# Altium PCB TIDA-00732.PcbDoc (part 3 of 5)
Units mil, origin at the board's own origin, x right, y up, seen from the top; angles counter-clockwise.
Board outline 8994.78 x 4186 mil, 6 copper layers (Top Layer, GND1, PWR1, PWR2, GND2, Bottom Layer), stack 97.668 mil thick; 693 components, 463 nets, 2087 pads, 616 vias.

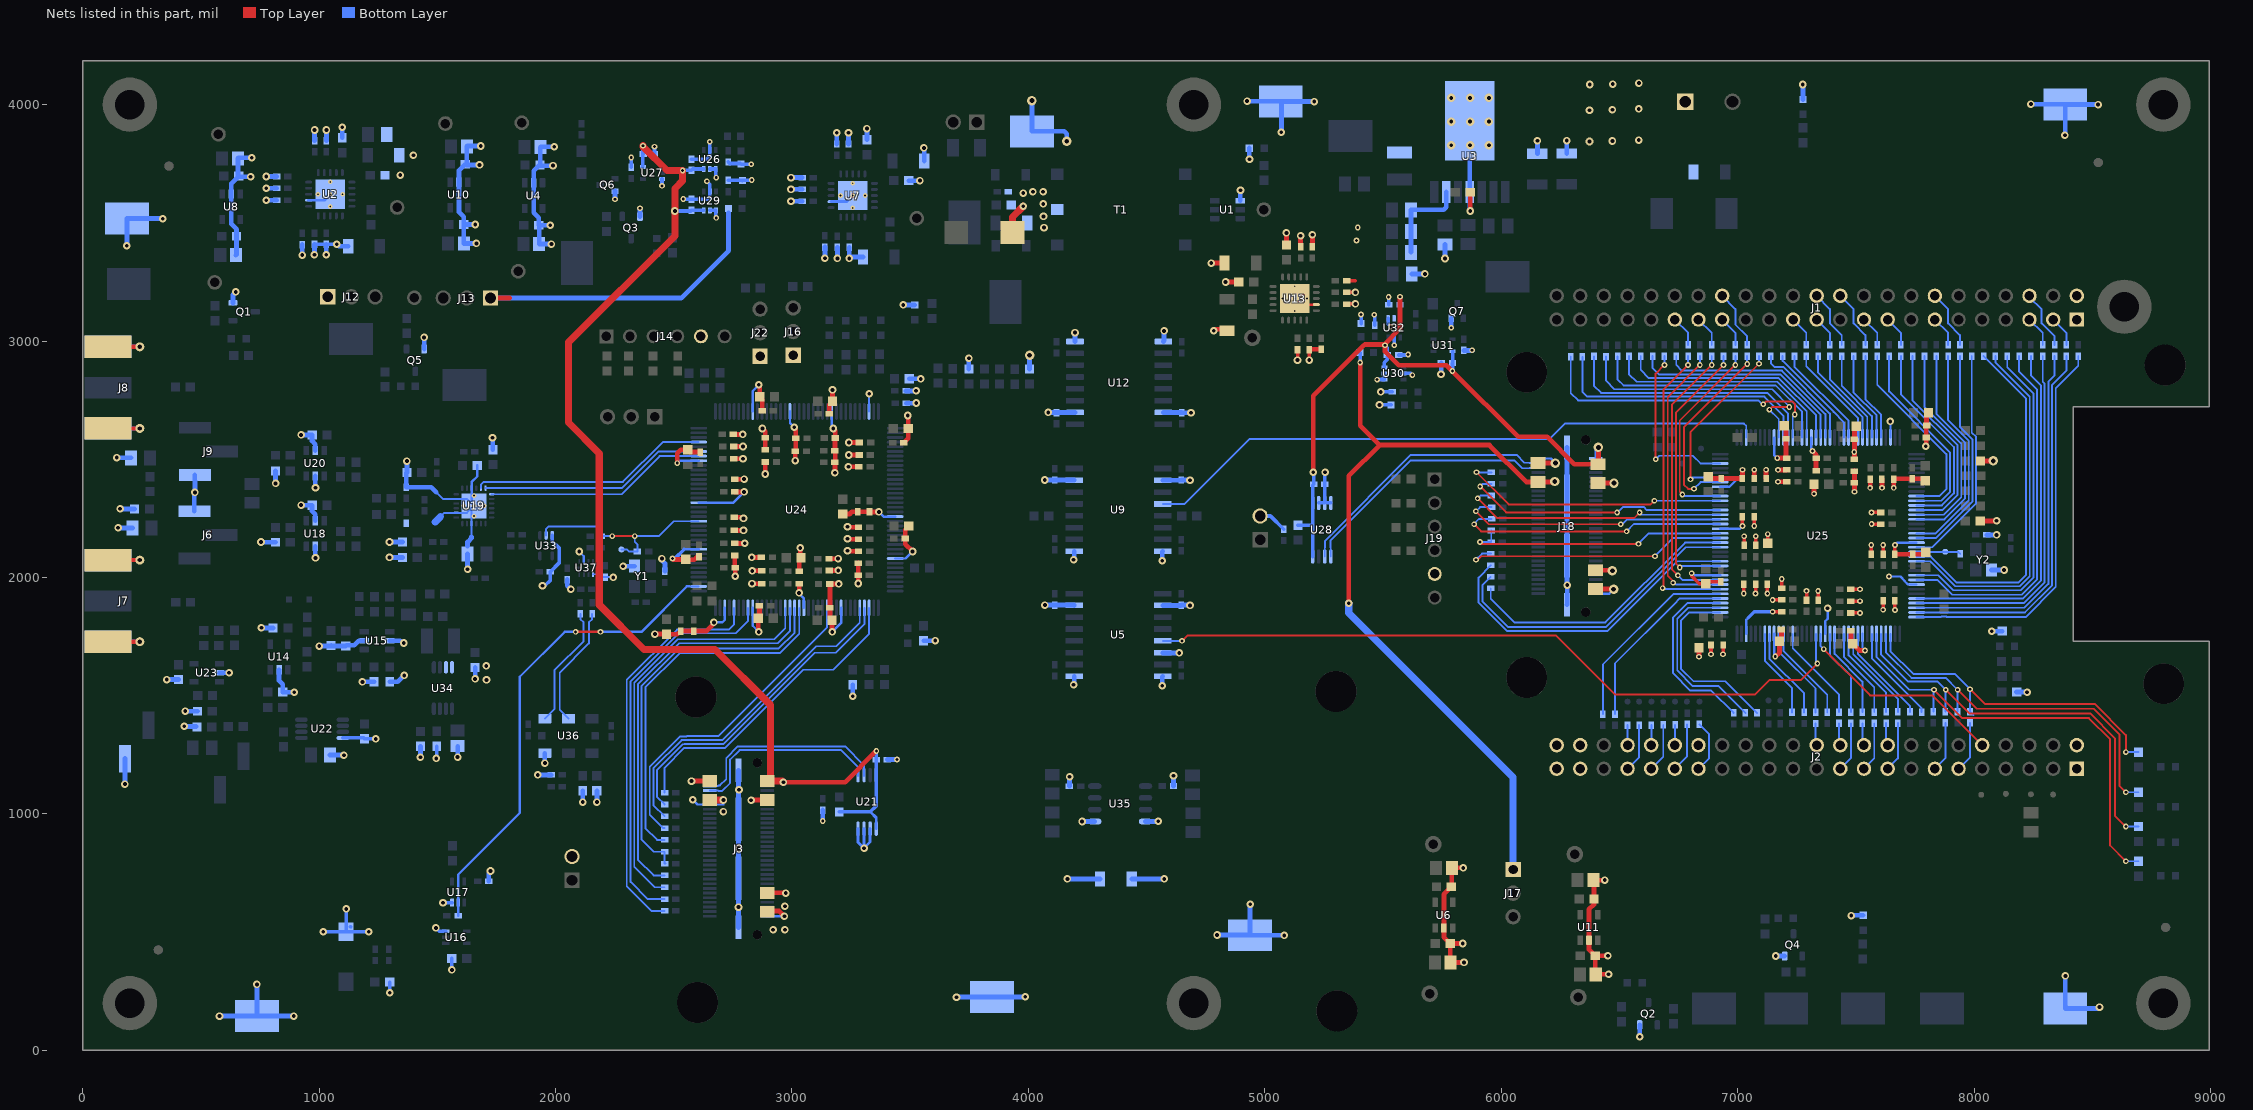
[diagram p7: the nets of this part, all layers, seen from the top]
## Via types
v1: diameter 32, hole 16, Top Layer to Bottom Layer, tented both sides, 393 vias
v2: diameter 24, hole 12, Top Layer to Bottom Layer, tented both sides, 174 vias
v3: diameter 19.68, hole 7.87, Top Layer to Bottom Layer, tented both sides, 20 vias
v4: diameter 40, hole 20, Top Layer to Bottom Layer, tented both sides, 19 vias
v5: diameter 36, hole 16, Top Layer to Bottom Layer, tented both sides, 9 vias
v6: diameter 24, hole 12, Top Layer to Bottom Layer, 1 vias

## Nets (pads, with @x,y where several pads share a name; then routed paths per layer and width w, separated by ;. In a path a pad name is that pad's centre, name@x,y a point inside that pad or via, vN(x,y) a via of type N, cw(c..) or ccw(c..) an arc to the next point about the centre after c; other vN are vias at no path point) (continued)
ADC_SDO1: U19.19 U24.138 | length 942.6
  Bottom Layer w8: U19.19@1729.8,2352.21 2279.21,2352.21 2440.38,2513.38 U24.138@2605.65,2513.38
ADC_SDO2: U19.18 U24.139 | length 965.7
  Bottom Layer w8: U19.18@1704.21,2377.8 2281.01,2377.8 2436.27,2533.06 U24.139@2605.65,2533.06
ADC_SDO3: U19.17 U24.141 | length 1010.6
  Bottom Layer w8: U19.17@1684.53,2377.8 1684.53,2393 1695.52,2404 2285,2404 2453.43,2572.43 U24.141@2605.65,2572.43
ADC_SRESETN: R93.1 U17.2 U24.110 | length 2034.4
  Top Layer w10: v2(2085,1770) v2(2190,1770)
  Bottom Layer w8: 2566.73,1962.2 U24.110@2605.65,1962.2
  Bottom Layer w10: R93.1@1587.75,568.73 1588.13,569.11 U17.2@1588.13,624.94 1588.13,743.1 1849,1003.97 1849,1580 2039,1770 v2(2085,1770) ; v2(2190,1770) 2363,1770 2555.2,1962.2 2566.73,1962.2
AGND_ISO: C2.2 C3.1 C4.2 C5.2 C6.2 C7.2 C9.2 C10.1 C12.2 C17.2 C18.2 C19.2 C20.2 C21.2 C22.2 C23.2 C24.1 C26.2 C31.2 C32.2 C33.2 C34.2 C35.2 C36.2 C37.2 C38.2 C44.1 C49.1 C50.1 C51.1 C53.2 C54.2 C55.1 C56.2 C57.2 C58.2 C59.2 C62.2 C63.1 C64.2 C65.2 C66.2 C69.2 C70.2 C71.2 C72.2 C75.1 C76.2 C77.1 C78.1 C79.2 C80.2 C81.2 C82.2 C83.2 C84.2 C85.2 C88.1 C92.2 C93.2 C94.2 C95.2 C96.2 C97.2 C98.2 C99.2 C100.2 C101.2 C102.2 C103.2 C104.2 C105.2 C106.2 C107.2 C108.2 C109.2 C110.2 C111.2 C112.2 C113.2 C114.2 C115.2 C116.2 C117.2 C118.2 C119.2 C120.2 C121.2 C122.2 C123.2 C124.2 C125.2 C126.2 C127.2 C128.1 C129.2 C130.2 C131.2 C132.2 C133.1 C134.2 C135.2 C136.2 C137.2 C138.2 C139.2 C140.2 C141.2 C142.2 C143.2 C144.2 C145.2 C146.2 C147.2 C148.2 C149.2 C150.2 C151.2 C152.2 C153.2 C154.2 C155.1 C192.1 C197.2 C219.1 C221.2 C228.1 C230.2 C231.2 C232.2 C233.2 C236.1 C237.2 D13.1 J3.60 J3.MP1 J3.MP2 J3.MP3 J3.MP4 J4.2 J6.1 J7.2 J7.3 J7.4 J7.5 J8.2 J8.3 J8.4 J8.5 J9.3 J11.2 J14.5 J16.1 J22.1 Q1.2 Q3.2 Q5.2 Q6.2 R46.2 R47.1 R53.1 R54.1 R55.1 R56.1 R57.1 R58.1 R59.1 R60.1 R64.1 R65.1 R66.1 R67.1 R68.1 R69.1 R70.1 R71.1 R88.1 R91.1 R96.1 R114.1 R158.1 R165.1 R168.1 R177.2 R249.1 R250.1 R253.1 R267.1 S1.1 T1.5 TP36.1 TP37.1 TP38.1 TP39.1 U2.7 U2.21 U4.2 U5.9 U5.15 U7.7 U7.21 U8.2 U9.9 U9.15 U10.2 U12.2 U12.8 U14.2 U15.2 U15.5 U16.3 U17.3 U18.2 U18.5 U19.4 U19.8 U19.11 U19.15 U19.25 U20.2 U20.5 U21.2 U21.3 U21.4 U22.4 U23.2 U24.9 U24.17 U24.26 U24.34 U24.56 U24.65 U24.81 U24.89 U24.100 U24.106 U24.118 U24.128 U24.137 U26.2 U27.3 U29.2 U33.3 U34.7 U34.8 U35.5 U36.3@1955,1257.17 U37.1 U37.7 Y1.2 | length 16929.3
  Top Layer w10: v1@2095,2110 v1(2100,2110)
  Top Layer w15: v2(2418.62,3822.38) v2@2420,3821 ; v2@2650,3841 v2(2652,3843)
  Top Layer w20: v1@1398.92,3785.92 v1(1399,3786) ; v1(2420.57,1760.57) C97.2@2469.36,1760.57 2470.42,1759.51 2515.43,1759.51 C101.2@2529.36,1773.44 C95.2@2584.36,1773.44 2638.44,1773.44 2670,1805 v1(2670,1810) ; v2(2495,2080) 2498.5,2076.5 C121.2@2551,2076.5 2552.5,2075 2586.5,2075 2599.88,2088.38 C114.2@2607,2088.38 ; v2(2515,2483.69) 2515,2525.5 2530,2540.5 C120.2@2559,2540.5 2568.87,2530.62 C113.2@2613,2530.62 ; v1(2575,1139) 2575.06,1138.94 C83.2@2652.5,1138.94 ; C115.2@2752.62,2605 v1(2792,2605) ; C127.2@2753.62,2502 v1(2793,2502) ; C126.2@2753.62,2554 v1(2793,2554) ; C109.2@2755.62,2199 v1(2795,2199) ; C103.2@2755.62,2255 2790,2255 v1(2795,2250) ; C100.2@2758.24,2362 v1(2797.62,2362) ; C94.2@2758.24,2416 v1(2797.62,2416) ; C124.2@2758.62,2093 2758.62,2043 C125.2@2759.62,2042 2759.62,2005.38 v1(2760,2005) ; C112.2@2758.62,2144 2799,2144 v1(2800,2145) ; v1(2827,1058) 2827.94,1058.94 C84.2@2895.5,1058.94 ; v1(2830,2085) C149.2@2870.38,2085 ; v1(2831,1974) C135.2@2871.38,1974 ; v1(2832,2028) C148.2@2872.38,2028 ; v1(2860,1770) 2857.57,1772.43 C142.2@2857.57,1827.36 2862.44,1832.24 C134.2@2862.44,1880.36 ; v1(2860,2815) 2863.5,2811.5 C145.2@2863.5,2765 2874.38,2754.13 C138.2@2874.38,2704.5 ; v1(2875,2630) 2887.38,2617.62 C141.2@2887.38,2591.5 2887.38,2541.5 C151.2@2886.38,2540.5 ; v1(2887.38,2437.62) C152.2@2887.38,2488.5 ; C82.2@2895.5,666.14 2972.86,666.14 v1(2974,665) ; v1(3010,2635) 3016.38,2628.62 C110.2@3016.38,2589.5 3016.38,2536.5 C104.2@3014.38,2534.5 v1(3014.38,2494.38) ; v1(3030,1935) 3030.62,1935.62 C108.2@3030.62,1974 ; C102.2@3030.62,2027 3030.62,2075.13 C106.2@3038.5,2083 3035,2086.5 v1(3035,2125) ; C147.2@3156.62,2079.5 3194.5,2079.5 v1(3195,2080) ; C146.2@3157.62,2029.5 3195.5,2029.5 v1(3196,2030) ; C140.2@3157.62,2692 3157.62,2731.13 C144.2@3171.5,2745 v1(3171.5,2793.5) ; v1(3170,1770) 3169.5,1770.5 C143.2@3169.5,1819 3160.62,1827.87 C136.2@3160.62,1872 3160.62,1971.5 C137.2@3159.62,1972.5 3197.5,1972.5 v1(3198,1973) ; v1(3175,2630) 3183.62,2621.38 C139.2@3183.62,2590 ; v1(3181.62,2442.62) C153.2@3181.62,2487 3183.62,2489 C139.2@3183.62,2590 ; C154.2@3181.62,2536 3181.62,2588 C139.2@3183.62,2590 ; C107.2@3215,2268.5 3243.5,2268.5 3253.38,2278.38 C111.2@3278,2278.38 3327,2278.38 C105.2@3328,2277.38 v1(3367.62,2277.38) ; v1(3235,2113) 3237,2111 C132.2@3281.38,2111 ; v1(3235,2164) 3237,2162 C131.2@3281.38,2162 ; v1(3235,2215) 3237,2213 C117.2@3281.38,2213 ; v1(3239,2468) C130.2@3283.38,2468 ; v1(3240,2518) C129.2@3284.38,2518 ; v1(3241,2571) C119.2@3285.38,2571 ; v1(3280.38,1974.62) C99.2@3280.38,2010 C93.2@3280.38,2061 ; C118.2@3473.62,2570 3491.5,2587.87 C123.2@3491.5,2630 3491.5,2683.5 v1(3490,2685) ; C122.2@3494.5,2218 3478.62,2202.13 C116.2@3478.62,2165 3478.62,2141.38 v1(3510,2110)
  Top Layer w30: C237.2@3933.09,3459 3933.09,3525.09 v1(3978,3570)
  Bottom Layer w8: 1496,2360 1523.47,2332.53 U19.11@1580.2,2332.53 1625.47,2332.53 1645.16,2312.84 v3(1655,2303) U19.25@1645.16,2293.16 ; 1513.24,2257.24 1529.47,2273.47 U19.8@1580.2,2273.47 1625.47,2273.47 U19.25@1645.16,2293.16 ; 1645.16,2171.03 U19.4@1645.16,2228.2 U19.25@1645.16,2293.16 ; U37.1@2159.17,2013.94 2176.22,2013.94 2188.27,2001.89 C231.2@2209.65,2001.89 2243.27,2001.89 v1(2244.65,2000.51)
  Bottom Layer w10: U19.25@1645.16,2312.84 U19.15@1645.16,2377.8 1645.16,2403.89 1669.5,2428.23 C62.2@1669.5,2474.19 ; v1(1733.5,2590.68) v1@1735,2589.19 ; v1(2100,2110) 2119.8,2090.2 U37.7@2119.8,2067.09 ; v2(2515,2483.69) 2525,2493.69 U24.137@2605.65,2493.69 ; 2545,2119.68 U24.118@2605.65,2119.68 ; v1(2575,1139) 2575.66,1138.34 J3.60@2652.5,1138.34 ; U24.128@2605.65,2316.53 2752.15,2316.53 v1(2797.62,2362) ; v1(2670,1810) 2705,1810 2715.88,1820.88 U24.106@2715.88,1871.65 ; U24.100@2833.99,1871.65 2833.99,1796.01 v1(2860,1770) ; U24.9@2833.99,2702.35 2833.99,2788.99 v1(2860,2815) ; U24.17@2991.47,2702.35 2991.47,2653.53 v1(3010,2635) ; v1(3030,1935) 3030,1931.09 3050.53,1910.57 U24.89@3050.53,1871.65 ; U24.26@3168.64,2702.35 3168.64,2636.36 v1(3175,2630) ; v1(3170,1770) 3208.01,1808.01 U24.81@3208.01,1871.65 ; U24.34@3326.12,2702.35 3326.12,2776.12 v1(3327,2777) ; v1(3367.62,2277.38) 3387.53,2257.47 U24.56@3436.35,2257.47 ; U24.65@3436.35,2080.31 3480.31,2080.31 v1(3510,2110)
  Bottom Layer w12: U2.7@955.98,3595.33 1021.93,3595.33 v3(1047.52,3620.92) ; U7.7@3165.65,3589.87 3231.59,3589.87 v3(3257.18,3615.46) ; U21.4@3279.61,937.81 3279.61,880.39 v1(3305,855) v1@3305.2,855.2 ; U21.3@3305.2,937.81 v1@3305.2,855.2 ; U21.2@3330.8,937.81 3330.8,880.8 v1@3305.2,855.2
  Bottom Layer w15: R54.1@980.52,3409.3 R53.1@1030.52,3409.3 v1(1075.02,3409.3) ; v1(1017.83,502.03) S1.1@1114.33,502.03 ; U22.4@1100.6,1321.61 1187.89,1321.61 C79.2@1192,1317.5 v1(1239.5,1317.5) v1@1239.2,1317.21 ; v1@1114.33,598.53 S1.1@1114.33,502.03 ; S1.1@1132.83,522.03 S1.1@1133.13,522.33 ; v1(1210.53,501.73) 1210.83,502.03 S1.1@1114.33,502.03 ; C56.2@1298.63,288.73 1298.63,243.23 v1(1299.13,243.73) ; v1(1494.13,517.73) 1508.04,503.82 U16.3@1535.84,503.82 ; v1(1496,1235) 1498,1237 R47.1@1498,1286.5 ; v1(1524.13,624.73) 1524.34,624.94 U17.3@1562.54,624.94 ; v1(1561.63,340.23) C50.1@1561.63,388.73 ; v1(1945,1965) 1955,1965 1978.62,1988.62 C192.1@1978.62,2025 2015,2061.38 2015,2125 1986.1,2153.9 U33.3@1986.1,2178.4 ; R250.1@2320,3734.62 v2(2320,3776) ; C133.1@2418.62,3791 v2(2418.62,3822.38) ; v2(2450.35,3656.35) U27.3@2450.35,3685.41 ; v2(2495,2080) 2505.32,2080 2545,2119.68 ; v2(2540,3601) 2541.38,3599.62 C155.1@2575,3599.62 2648.62,3599.62 2653,3604 U29.2@2653,3633.35 2653,3663 v2(2640,3676) ; C128.1@2575,3769.62 2638.62,3769.62 2652,3783 U26.2@2652,3808.35 v2(2652,3843) ; C221.2@2730,3679.62 2789.38,3679.62 R253.1@2790,3679 2792,3681 v2(2830,3681) ; C150.2@2730,3757.38 2736.38,3751 2782,3751 R249.1@2785,3748 v2(2828,3748)
  Bottom Layer w20: v1(144,2507) 145,2506 C76.2@205,2506 ; v1(150,2210) 151,2209 C64.2@211,2209 ; v1(158.5,2291) 159.5,2290 R96.1@219.5,2290 ; v1(179,1126.02) J11.2@179,1234.16 ; v1(187,3403) 188,3404 TP36.1@188,3518 338,3518 v1(339,3517) ; v1(356,1568.02) 356.5,1568.53 C77.1@405,1568.53 ; v1(429.5,1371.02) 430.5,1370.02 R114.1@481.01,1370.02 ; v1(434,1435.02) 435,1434.02 C80.2@485.5,1434.02 ; J6.1@472.5,2280 472.5,2357.5 v1(475,2360) 475,2409.5 474.5,2410 J9.3@474.5,2433 ; v1(579,145) TP37.1@737,145 ; U23.2@579.13,1597.02 v1(619.51,1597.02) ; Q1.2@635.76,3161.4 635.76,3195.76 v1(648,3208) ; C33.2@647.97,3363 651,3366.03 C34.2@651,3443 651,3473 628.5,3495.5 U8.2@628.5,3622.13 628.5,3666.08 660,3697.57 C32.2@660,3698 ; C32.2@656.97,3694.54 C32.2@656.97,3694.97 ; v1(710.47,3694.97) C32.2@656.97,3694.97 ; v1(715.47,3774.97) 658.94,3774.97 C31.2@656.97,3773 C32.2@656.97,3694.97 ; v1(737,279) TP37.1@737,145 ; v1(754.5,2150) 755.5,2149 C65.2@815.5,2149 ; v1(756,1787) 757,1786 C55.1@805.5,1786 ; v1(776.39,3595.92) R56.1@820.9,3595.92 ; v1(776.39,3645.92) R57.1@820.9,3645.92 ; v1(776.39,3695.92) R58.1@820.9,3695.92 ; C70.2@815.5,2451 815.5,2398.5 v1(816,2398) ; U14.2@831,1609.87 831,1564 846.5,1548.5 C53.2@846.5,1515 v1(895,1515) ; v1(893,145) TP37.1@737,145 ; v1(924,2306) C228.1@970.5,2306 970.5,2280.5 984,2267 U18.5@984,2240.13 ; v1(924,2603) C219.1@970.5,2603 970.5,2577.5 984,2564 U20.5@984,2537.13 ; v1(929.08,3363.39) R55.1@929.08,3407.9 ; v1(980.52,3364.8) R54.1@980.52,3409.3 ; R59.1@981,3848 v1(981,3892.5) ; U18.2@984,2131.87 984,2084 v1(985,2083) ; U20.2@984,2428.87 984,2381 v1(985,2380) ; v1(1001,1710) 1048.5,1710 R91.1@1051,1712.5 1053,1710.5 C49.1@1113,1710.5 1116.48,1713.98 1149,1713.98 1168.02,1733 U15.5@1190.87,1733 ; v1(1030.52,3364.8) R53.1@1030.52,3409.3 ; R60.1@1031,3848 v1(1031,3892.5) ; C81.2@1046,1249 1105,1249 v1(1105,1248) ; v1(1075.02,3409.3) 1083.32,3401 C9.2@1123.07,3401 ; C10.1@1098,3859.5 v1(1098,3904) ; v1(1183.5,1558.5) R88.1@1233,1558.5 ; v1(1298,2085) C57.2@1352.5,2085 ; v1(1298,2150) C58.2@1352.5,2150 ; C54.2@1299,1558.5 1332.5,1558.5 v1(1360,1586) ; U15.2@1299.13,1733 1343,1733 1353,1723 v1(1358,1723) ; v1(1371.5,2492.5) C72.2@1371.5,2444 1369,2441.5 C71.2@1369,2381.62 1474.38,2381.62 1496,2360 ; v1(1428.59,1240) 1428.8,1240.2 C197.2@1428.8,1285.91 ; v1(1444,3015.2) 1444.4,3015.6 Q5.2@1444.4,2966.24 ; v1(1585.8,1240.63) 1586,1240.83 C88.1@1586,1286.54 ; C36.2@1618,3748 1592.39,3722.39 1592.39,3721.97 1591.5,3721.08 U10.2@1591.5,3672.13 1591.5,3545.92 1612,3525.42 C38.2@1612,3493 ; C36.2@1624.97,3744.54 C36.2@1624.97,3744.97 ; v1(1628,2035) C69.2@1628,2099 ; 1628,2133.5 1628,2150 1645.16,2167.16 1645.16,2171.03 1643.77,2172.42 ; v1(1660,1571) R46.2@1660,1619.5 ; v1(1660.5,3493) C38.2@1612,3493 ; v1(1665.5,3413) C37.2@1612.97,3413 1612,3413.97 C38.2@1612,3493 ; v1(1678.47,3744.97) C36.2@1624.97,3744.97 ; v1(1683.47,3824.97) 1626.94,3824.97 C35.2@1624.97,3823 C36.2@1624.97,3744.97 ; C51.1@1717.75,715.73 1717.75,749.35 1725.13,756.73 v1(1725.13,758.73) ; C63.1@1735,2540.68 v1@1735,2589.19 ; v1(1925,1165) R267.1@1981.38,1165 ; C20.2@1934,3745 1908.39,3719.39 1908.39,3718.97 1907.5,3718.08 U4.2@1907.5,3669.13 1907.5,3542.5 1929,3521 C22.2@1929,3490 ; C20.2@1935.97,3741.54 C20.2@1935.97,3741.97 ; v1(1955,1215) U36.3@1955,1257.17 ; v1(1977.5,3490) C22.2@1929,3490 ; v1(1982.5,3410) C21.2@1930.97,3410 1930.97,3488.03 C22.2@1929,3490 ; v1(1989.47,3741.97) C20.2@1935.97,3741.97 ; v1(1994.47,3821.97) 1937.94,3821.97 C19.2@1935.97,3820 C20.2@1935.97,3741.97 ; C59.2@2050,1991.38 2050,1965 v1(2065,1950) ; v1(2115,1050) C232.2@2115,1098.5 ; v1(2175,1050) C233.2@2175,1098.5 ; v2(2251.5,3600) Q6.2@2251.5,3634.41 ; v1(2285.65,2047.51) 2285.95,2047.82 Y1.2@2334.18,2047.82 ; Q3.2@2357.4,3527.24 v2(2357.4,3561.65) ; v1(2450,2080) 2450,2073.4 2462.65,2060.76 C85.2@2462.65,2026.13 ; J3.MP1@2774,520.04 v1(2774,606) J3.MP2@2774,727.54 v1(2774,854) J3.MP3@2774,977.54 2774,1100 v1(2776,1102) 2774,1104 J3.MP4@2774,1185.04 ; v1(2996.06,3591.46) R67.1@3043.56,3591.46 ; v1(2996.06,3641.46) R68.1@3043.56,3641.46 ; v1(2996.06,3691.46) R69.1@3043.56,3691.46 ; v2(3130,970) C78.1@3130,1016.38 ; v1(3139.54,3350.06) R66.1@3139.54,3397.56 ; v1@3170,2795 v1(3171.5,2793.5) ; R70.1@3189.18,3833.46 v1(3189.18,3880.97) ; v1(3192.18,3349.34) R65.1@3192.18,3396.84 ; R71.1@3239.18,3833.46 v1(3239.18,3880.97) ; R64.1@3242.18,3396.84 v1(3242.18,3349.34) 3247.84,3355 C23.2@3300.07,3355 ; R165.1@3256.8,1546.5 3256.8,1498 v1(3257.3,1497.5) ; C24.1@3317.18,3850.96 v1(3317.18,3898.46) ; C75.1@3403.62,1230 v2(3444,1230) ; v1(3471,3153) 3471.5,3152.5 D13.1@3519,3152.5 ; C98.2@3482.62,2789 3524,2789 v1(3525,2790) ; C92.2@3483.62,2737 3525,2737 v1(3526,2738) ; C18.2@3493.68,3678.46 v1(3541.18,3678.46) ; C96.2@3496.5,2840 v1(3545,2840) ; R168.1@3557,1732.5 3605.5,1732.5 v1(3606,1733) ; v1(3558,3817) 3559.11,3815.89 C17.2@3559.11,3761.46 ; v1(3696,225) 3697,226 TP39.1@3846,226 3986,226 v1(3987,227) ; R158.1@3748.2,2881.5 v1(3748.2,2927.5) ; R177.2@4005,2881.5 v4(4005,2940) ; v4(4015,4017) TP38.1@4015,3887 4152,3887 4162,3877 v4(4162,3845) ; v1(4069.63,1883.37) C12.2@4111.01,1883.37 4192.62,1883.37 U5.15@4194,1881.99 ; v1(4069.62,2412.36) C26.2@4111,2412.36 4192.61,2412.36 U9.15@4193.99,2410.98 ; v1(4084,2698) 4117.62,2698 C44.1@4119,2696.62 4120.38,2698 U12.2@4196.99,2698 ; v1(4165,725) C236.1@4303.07,725 ; C230.2@4173.38,1117 4173.38,1156.38 v1(4174,1157) ; v1(4191,2075) 4193.99,2077.99 U9.9@4193.99,2110.98 ; v1(4191.01,1546.01) 4194,1549 U5.9@4194,1581.99 ; U12.8@4196.99,2998 v1(4196.99,3035.99) ; v1(4227,968) U35.5@4280.72,968
  Bottom Layer w30: 1491.38,2235.38 1513.24,2257.24
  other v1: 1114.63,598.23 1708,1567 1707,1626 4066,3480 4064,3527 4063,3580 3978,3626 4019,3631 4062,3631 1343,3702
  other v3: 1655,2259.69 1611.69,2303 1698.31,2303 1655,2346.31 3257.18,3563.3 1047.52,3568.76 3205.02,3615.46 3309.35,3615.46 995.35,3620.92 1099.69,3620.92 3257.18,3667.63 1047.52,3673.09
AIN0: J2.39 R149.2 | length 204.7
  Bottom Layer w8: J2.39@6534,1191 6583,1240 R149.2@6583,1375.38
AIN1: J2.40 R150.1 | length 84.4
  Bottom Layer w8: J2.40@6534,1291 R150.1@6534,1375.38
AIN2: J2.37 R147.2 | length 206.5
  Bottom Layer w8: J2.37@6634,1191 6685,1242 R147.2@6685,1376.38
AIN3: J2.38 R148.1 | length 84.8
  Bottom Layer w8: J2.38@6634,1291 6635,1292 R148.1@6635,1375.38
AIN4: J2.33 R144.2 | length 223
  Bottom Layer w8: J2.33@6834,1191 6879,1236 6879,1337.38 R144.2@6838,1378.38
AIN5: J2.36 R146.1 | length 85.8
  Bottom Layer w8: J2.36@6734,1291 6734,1375.38 R146.1@6735,1376.38
AIN6: J2.35 R145.2 | length 208.9
  Bottom Layer w8: J2.35@6734,1191 6786,1243 R145.2@6786,1378.38
BBB_ADC_CSN: R41.1 U25.12 | length 1094.7
  Bottom Layer w8: R41.1@6392,2935.38 6392,2811 6422.4,2780.6 7125.09,2780.6 7213.05,2692.64 U25.12@7213.05,2592.35
BBB_ADC_RESETN: R37.1 U25.18 | length 972.7
  Bottom Layer w8: R37.1@6590,2936.38 6590,2878 6624.6,2843.4 7173.73,2843.4 7331.16,2685.97 U25.18@7331.16,2592.35
BBB_ADC_RVS: R36.2 U25.20 | length 852.8
  Bottom Layer w8: R36.2@6740,2936.38 6740,2898.8 6764,2874.8 7186.73,2874.8 7370.53,2691 U25.20@7370.53,2592.35
BBB_ADC_SCLK: R43.1 U25.13 | length 1276.2
  Top Layer w8: v2(7108,2733) 7119.8,2744.8 7231.2,2744.8 7241.8,2734.2 7241.8,2689.8 v2(7241,2689)
  Bottom Layer w8: R43.1@6294,2934 6294,2780 6324.8,2749.2 7087.8,2749.2 7104,2733 v2(7108,2733) ; U25.13@7232.73,2592.35 7232.73,2680.73 v2(7241,2689)
BBB_ADC_SDI: R39.1 U25.15 | length 1043.2
  Bottom Layer w8: R39.1@6492,2935.38 6492,2837 6517,2812 7160.72,2812 7272.1,2700.62 U25.15@7272.1,2592.35
BBB_ADC_SDO0: R38.2 U25.19 | length 939.8
  Bottom Layer w8: R38.2@6640,2936.38 6640,2885 6665.9,2859.1 7180.23,2859.1 7350.84,2688.49 U25.19@7350.84,2592.35
BBB_ADC_SDO1: R40.2 U25.16 | length 1003.9
  Bottom Layer w8: R40.2@6540,2936.38 6540,2860 6572.3,2827.7 7167.22,2827.7 7291.79,2703.14 U25.16@7291.79,2592.35
BBB_ADC_SDO2: R42.2 U25.10 | length 1150.6
  Top Layer w8: v2(7134,2710) 7145.1,2721.1 v2(7218.1,2721.1)
  Bottom Layer w8: R42.2@6443,2934.38 6443,2832 6478.7,2796.3 7145.11,2796.3 7220.3,2721.1 v2(7218.1,2721.1) ; v2(7134,2710) 7173.68,2670.32 U25.10@7173.68,2592.35
BBB_ADC_SDO3: R44.2 U25.11 | length 1132.3
  Bottom Layer w8: R44.2@6343,2933.38 6343,2785 6363.1,2764.9 7112.62,2764.9 7193.36,2684.15 U25.11@7193.36,2592.35
BBB_GPI0: R138.2 U25.102 | length 379.6
  Bottom Layer w8: U25.102@7114.62,1761.65 7114.62,1648.38 7229.5,1533.5 R138.2@7229.5,1429.62
BBB_GPIO0: R1.1 U25.71 | length 1615.3
  Bottom Layer w8: U25.71@7756.35,1852.2 8214.99,1852.2 8329.3,1966.5 8329.3,2814.3 8390,2875 R1.1@8390,2936.38
BBB_GPIO1: R3.1 U25.69 | length 1538.1
  Bottom Layer w8: U25.69@7756.35,1891.57 8209.96,1891.57 8297.9,1979.51 8297.9,2819.51 8290,2827.41 R3.1@8290,2936.38
BBB_GPIO2: R5.1 U25.64 | length 1539
  Bottom Layer w8: U25.64@7756.35,1989.99 7844,1989.99 7907.04,1926.95 8200.94,1926.95 8266.5,1992.52 8266.5,2793.5 8190,2870 R5.1@8190,2936.38
BBB_GPIO3: R7.1 U25.60 | length 1531.1
  Bottom Layer w8: U25.60@7756.35,2068.73 7814.27,2068.73 7920,1963 8192.58,1963 8235.1,2005.52 8235.1,2764.9 8090,2910 R7.1@8090,2936.38
BBB_GPIO4: R11.1 U25.54 | length 924.1
  Bottom Layer w8: U25.54@7756.35,2186.84 7836.98,2186.84 7976.9,2326.76 7976.9,2577.91 7890,2664.81 R11.1@7890,2936.38
BBB_GPIO5: R13.1 U25.50 | length 880.9
  Bottom Layer w8: U25.50@7756.35,2265.58 7871.32,2265.58 7945.5,2339.77 7945.5,2564.91 7790,2720.41 R13.1@7790,2936.38
BBB_GPIO6: R15.1 U25.48 | length 852.2
  Bottom Layer w8: R15.1@7690,2936.38 7690,2776 7914.1,2551.9 7914.1,2355.9 7863.16,2304.95 U25.48@7756.35,2304.95
BBB_GPIO7: R17.1 U25.46 | length 822.4
  Bottom Layer w8: R17.1@7590,2936.38 7590,2814.52 7882.7,2521.82 7882.7,2373.7 7853.32,2344.32 U25.46@7756.35,2344.32
BBB_GPIO8: R19.1 U25.31 | length 384.2
  Bottom Layer w8: R19.1@7490,2936.38 7490,2782.33 7587.06,2685.27 U25.31@7587.06,2592.35
BBB_GPIO9: R21.1 U25.29 | length 409.3
  Bottom Layer w8: R21.1@7390,2936.38 7390,2837.92 7547.69,2680.23 U25.29@7547.69,2592.35
BBB_GPIO10: R23.1 U25.27 | length 434.5
  Bottom Layer w8: R23.1@7290,2936.38 7290,2893.52 7508.32,2675.19 U25.27@7508.32,2592.35
BBB_GPIO11: R25.1 U25.24 | length 451.4
  Bottom Layer w8: R25.1@7190,2936.38 7190,2916 7405.5,2700.5 7405.5,2700.44 7449.27,2656.67 U25.24@7449.27,2592.35
BBB_GPIO12: R27.1 U25.139 | length 770.5
  Top Layer w8: v2(6800,2415) 6800,2614 v2(7090,2904)
  Bottom Layer w8: v2(6800,2415) 6808.06,2423.06 U25.139@6925.65,2423.06 ; v2(7090,2904) R27.1@7090,2936.38
BBB_GPIO13: R29.1 U25.135 | length 849.7
  Top Layer w8: v2(6766,2351) 6755,2362 6755,2664 v2(6990,2899)
  Bottom Layer w8: v2(6766,2351) 6772.68,2344.32 U25.135@6925.65,2344.32 ; v2(6990,2899) R29.1@6990,2936.38
BBB_GPIO14: R31.1 U25.117 | length 1193.8
  Top Layer w8: v2(6747,2009) 6722,2034 6722,2731 v2(6890,2899)
  Bottom Layer w8: v2(6747,2009) 6766.01,1989.99 U25.117@6925.65,1989.99 ; v2(6890,2899) R31.1@6890,2936.38
BBB_GPIO15: R33.1 U25.115 | length 1270.8
  Top Layer w8: v2(6682.53,1955) 6686,1958.47 6686,2795 v2(6790,2899)
  Bottom Layer w8: v2(6682.53,1955) 6686.91,1950.62 U25.115@6925.65,1950.62 ; v2(6790,2899) R33.1@6790,2936.38
BBB_GPIO16: R35.1 U25.142 | length 744.2
  Top Layer w8: v2(6653,2500) 6653,2862 v2(6690,2899)
  Bottom Layer w8: v2(6653,2500) 6668,2515 6810,2515 6842.88,2482.12 U25.142@6925.65,2482.12 ; v2(6690,2899) R35.1@6690,2936.38
BBB_GPIO17: R4.2 U25.70 | length 1573.4
  Bottom Layer w8: U25.70@7756.35,1871.88 8212.48,1871.88 8313.6,1973.01 8313.6,2828.6 8340,2855 R4.2@8340,2936.38
BBB_GPIO18: R6.2 U25.68 | length 1524.7
  Bottom Layer w8: U25.68@7756.35,1911.25 8207.44,1911.25 8282.2,1986.01 8282.2,2812.8 8240,2855 R6.2@8240,2936.38
BBB_GPIO19: R8.2 U25.63 | length 1526
  Bottom Layer w8: U25.63@7756.35,2009.68 7848.32,2009.68 7912,1946 8197.78,1946 8250.8,1999.02 8250.8,2779.2 8140,2890 R8.2@8140,2936.38
BBB_GPIO20: R12.2 U25.55 | length 937.6
  Bottom Layer w8: U25.55@7756.35,2167.16 7839.5,2167.16 7992.6,2320.26 7992.6,2584.42 7940,2637.02 R12.2@7940,2936.38
BBB_GPIO21: R14.2 U25.51 | length 894.4
  Bottom Layer w8: U25.51@7756.35,2245.9 7873.83,2245.9 7961.2,2333.26 7961.2,2571.41 7840,2692.61 R14.2@7840,2936.38
BBB_GPIO22: R16.2 U25.49 | length 865.6
  Bottom Layer w8: R16.2@7740,2936.38 7740,2748.2 7929.8,2558.4 7929.8,2349.39 7865.67,2285.27 U25.49@7756.35,2285.27
BBB_GPIO23: R18.2 U25.47 | length 838.7
  Bottom Layer w8: R18.2@7640,2936.38 7640,2786.72 7898.4,2528.32 7898.4,2362.4 7860.64,2324.64 U25.47@7756.35,2324.64
BBB_GPIO24: R20.2 U25.32 | length 371.7
  Bottom Layer w8: R20.2@7540,2936.38 7540,2754.53 7606.75,2687.78 U25.32@7606.75,2592.35
BBB_GPIO25: R22.2 U25.30 | length 396.8
  Bottom Layer w8: R22.2@7440,2936.38 7440,2810.13 7567.38,2682.75 U25.30@7567.38,2592.35
BBB_GPIO26: R24.2 U25.28 | length 421.9
  Bottom Layer w8: R24.2@7340,2936.38 7340,2865.72 7528.01,2677.71 U25.28@7528.01,2592.35
BBB_GPIO27: R26.2 U25.25 | length 438.9
  Bottom Layer w8: R26.2@7240,2936.38 7240,2892 7468.95,2663.05 U25.25@7468.95,2592.35
BBB_GPIO28: R28.2 U25.21 | length 469.8
  Bottom Layer w8: R28.2@7140,2936.38 7140,2906 7155.5,2890.5 7193.24,2890.5 7390.21,2693.52 U25.21@7390.21,2592.35
BBB_GPIO29: R30.2 U25.138 | length 827.2
  Top Layer w8: v2(6815,2375) 6790,2375 6772,2393 6772,2635 v2(7040,2903)
  Bottom Layer w8: v2(6815,2375) 6843.38,2403.38 U25.138@6925.65,2403.38 ; v2(7040,2903) R30.2@7040,2936.38
BBB_GPIO30: R32.2 U25.120 | length 1157.8
  Top Layer w8: v2(6755,2042) 6739,2058 6739,2698 v2(6940,2899)
  Bottom Layer w8: v2(6755,2042) 6762.05,2049.05 U25.120@6925.65,2049.05 ; v2(6940,2899) R32.2@6940,2936.38
BBB_GPIO31: R34.2 U25.116 | length 1226.2
  Top Layer w8: v2(6726.77,1978) 6726.77,1984.23 6704,2007 6704,2763 v2(6840,2899)
  Bottom Layer w8: v2(6726.77,1978) 6733,1978 6740.69,1970.31 U25.116@6925.65,1970.31 ; v2(6840,2899) R34.2@6840,2936.38
BBB_GPIO32: R2.2 U25.72 | length 1659.8
  Bottom Layer w8: U25.72@7756.35,1832.51 7859,1832.51 7862.18,1835.7 7881.82,1835.7 7885,1832.51 8217.51,1832.51 8345,1960 8345,2800 8440,2895 R2.2@8440,2936.38
BBB_GPIO35: R127.1 U25.79 | length 418.1
  Bottom Layer w8: U25.79@7567.38,1761.65 7567.38,1657.62 7777.5,1447.5 R127.1@7777.5,1430.62
BBB_GPIO36: R129.1 U25.83 | length 408.3
  Bottom Layer w8: U25.83@7488.64,1761.65 7488.64,1675.36 7677.5,1486.5 R129.1@7677.5,1431.62
BBB_GPIO37: R131.1 U25.85 | length 384.1
  Bottom Layer w8: U25.85@7449.27,1761.65 7449.27,1664.73 7577.5,1536.5 R131.1@7577.5,1430.62
BBB_GPIO38: R133.1 U25.88 | length 367.6
  Bottom Layer w8: U25.88@7390.21,1761.65 7390.21,1671.79 7478.5,1583.5 R133.1@7478.5,1430.62
BBB_GPIO39: R135.1 U25.98 | length 408.7
  Bottom Layer w8: U25.98@7193.36,1761.65 7193.36,1689.64 7378.5,1504.5 R135.1@7378.5,1429.62
BBB_GPIO40: R137.1 U25.101 | length 392.6
  Bottom Layer w8: U25.101@7134.31,1761.65 7134.31,1657.18 7280.5,1510.98 R137.1@7280.5,1429.62
BBB_GPIO42: R141.1 U25.110 | length 782.5
  Bottom Layer w8: U25.110@6925.65,1852.2 6794.2,1852.2 6760,1818 6760,1614 6813,1561 6948.12,1561 R141.1@7081.5,1427.62
BBB_GPIO43: R143.1 U25.112 | length 785.1
  Bottom Layer w8: U25.112@6925.65,1891.57 6786.57,1891.57 6727,1832 6727,1595 6800,1522 6888.12,1522 R143.1@6982.5,1427.62
BBB_GPIO44: R151.1 U25.113 | length 773.6
  Bottom Layer w8: R151.1@6481,1421.62 6481,1637 6731,1887 6755.25,1911.25 U25.113@6925.65,1911.25
BBB_GPIO47: R128.2 U25.82 | length 421.2
  Bottom Layer w8: U25.82@7508.32,1761.65 7508.32,1677.88 7728.5,1457.7 R128.2@7728.5,1431.62
BBB_GPIO48: R130.2 U25.84 | length 395.7
  Bottom Layer w8: U25.84@7468.95,1761.65 7468.95,1670.78 7627.5,1512.23 R130.2@7627.5,1431.62
BBB_GPIO49: R132.2 U25.87 | length 379.7
  Bottom Layer w8: U25.87@7409.9,1761.65 7409.9,1677.1 7527.5,1559.5 R132.2@7527.5,1430.62
BBB_GPIO50: R134.2 U25.96 | length 412.1
  Bottom Layer w8: U25.96@7232.73,1761.65 7232.73,1700.27 7428.5,1504.5 R134.2@7428.5,1430.62
BBB_GPIO52: R142.2 U25.111 | length 781.6
  Bottom Layer w8: U25.111@6925.65,1871.88 6790.88,1871.88 6744.3,1825.3 6744.3,1606.7 6810,1541 6919.12,1541 R142.2@7032.5,1427.62
BBB_GPIO53: R152.2 U25.114 | length 829.8
  Bottom Layer w8: R152.2@6430,1421.62 6430,1632 6728.94,1930.94 U25.114@6925.65,1930.94
BBB_GPIO54: R136.2 U25.99 | length 396.6
  Bottom Layer w8: U25.99@7173.68,1761.65 7173.68,1686.32 7329.5,1530.5 R136.2@7329.5,1429.62
BBB_GPO0: R9.1 U25.57 | length 959.2
  Bottom Layer w8: U25.57@7756.35,2127.79 7822.33,2127.79 8008.3,2313.75 8008.3,2594.72 7990,2613.02 R9.1@7990,2936.38
BBB_GPO1: R10.2 U25.59 | length 1521
  Bottom Layer w8: U25.59@7756.35,2088.42 7816.79,2088.42 7926.5,1978.7 8186.08,1978.7 8219.4,2012.02 8219.4,2756.98 R10.2@8040,2936.38
BBB_I2C2_SCL: J2.19 R131.2 | length 210.4
  Bottom Layer w8: J2.19@7534,1191 7577.5,1234.5 R131.2@7577.5,1383.38
BBB_I2C_SDA: J2.20 R132.1 | length 95.1
  Bottom Layer w8: R132.1@7527.5,1383.38 7527.5,1297.5 J2.20@7534,1291
BBB_SYS_RESETN: J2.10 U25.90 | length 909
  Top Layer w8: v2(7364,1697) 7559.7,1501.3 7823.7,1501.3 J2.10@8034,1291
  Bottom Layer w8: U25.90@7350.84,1761.65 7350.84,1709.47 v2@7364,1696.31
BCLK: R180.2 TP49.1 U25.58 | length 190.3
  Bottom Layer w8: U25.58@7756.35,2108.1 7756.96,2107.5 TP49.1@7879.5,2107.5 ; TP49.1@7878,2109 TP49.1@7879.5,2107.5 ; R180.2@7941,2099.62 7933.13,2107.5 TP49.1@7879.5,2107.5
BCLK_ISO: R167.2 R269.2 TP48.1 U24.124 U33.2 | length 875.5
  Top Layer w8: v2(2240,2175) v2(2335,2175)
  Bottom Layer w8: U33.2@1960.1,2178.4 1960.1,2205.2 1970,2215.1 2179.9,2215.1 2193.62,2201.38 R269.2@2193.62,2175 v2(2240,2175) ; TP48.1@2278.65,2118.51 2301.49,2118.51 2310,2110 R167.2@2346.38,2110 2346.38,2140 2335,2151.38 v2(2335,2175) 2437.21,2175 2500,2237.79 U24.124@2605.65,2237.79
BCLK_N: C235.1 U36.5@2055,1402.83 | length 515.6
  Bottom Layer w8: U36.5@2055,1402.83 2018,1439.83 2018,1598 2141.5,1721.5 2141.5,1810.13 2155,1823.63 C235.1@2155,1846.38
BCLK_P: C234.1 U36.4@1955,1402.83 | length 516.9
  Bottom Layer w8: U36.4@1955,1402.83 1995,1442.83 1995,1607.53 2118.5,1731.03 2118.5,1810.13 2105,1823.63 C234.1@2105,1846.38
CONVST: U5.5 U25.91 | length 3063
  Top Layer w8: v2(4650,1731.99) 4672.01,1754 6232,1754 6480.3,1505.7 7073.7,1505.7 7134,1566 7267,1566 v2(7337,1636)
  Bottom Layer w8: U5.5@4568.02,1731.99 v2(4650,1731.99) ; U25.91@7331.16,1761.65 7331.16,1641.84 v2(7337,1636)
CSN: U9.4 U25.3 | length 2661.6
  Bottom Layer w8: U9.4@4568.01,2310.98 4660.98,2310.98 4935,2585 6202.8,2585 6268.8,2651 7026,2651 7035.88,2641.12 U25.3@7035.88,2592.35
EVM1_1.25V_1: U26.4 U26.5 | length 63.2
  Bottom Layer w15: U26.5@2652,3727.65 U26.4@2677.59,3727.65 2677.59,3693.41 v2(2680,3691)
EVM1_1.25V_2: U29.4 U29.5 | length 57.8
  Bottom Layer w15: U29.5@2653,3552.65 U29.4@2678.59,3552.65 2678.59,3522.41 v2(2680,3521)
EVM1_2.25V_2: U32.5
EVM1_ADC_CONVST: R163.1 U24.93 | length 1763.1
  Bottom Layer w8: R163.1@2461.38,690 2420,690 2332.9,777.1 2332.9,1554.51 2517.39,1739 2926,1739 2971.79,1784.79 U24.93@2971.79,1871.65
EVM1_ADC_CSN: R164.1 U24.92 | length 1716.3
  Bottom Layer w8: R164.1@2461.38,740 2415,740 2348.6,806.4 2348.6,1548.01 2522.59,1722 2940,1722 2991.47,1773.47 U24.92@2991.47,1871.65
EVM1_ADC_RESETN: R160.1 U24.104 | length 1696.6
  Bottom Layer w8: R160.1@2461.38,590 2405,590 2301.5,693.5 2301.5,1567.52 2513.98,1780 2732,1780 2755.25,1803.25 U24.104@2755.25,1871.65
EVM1_ADC_RVS: R170.1 U24.90 | length 1551.7
  Bottom Layer w8: R170.1@2461.38,890 2430,890 2380,940 2380,1535 2525,1680 2949,1680 3030.84,1761.84 U24.90@3030.84,1871.65
EVM1_ADC_SCLK: R166.1 R169.1 U24.91 | length 1668.8
  Bottom Layer w8: R166.1@2461.38,790 2465,790 2461.38,793.62 R169.1@2461.38,840 2415,840 2364.3,890.7 2364.3,1541.5 2521.8,1699 2943,1699 3011.16,1767.16 U24.91@3011.16,1871.65
EVM1_ADC_SDI: R162.1 U24.101 | length 1681
  Bottom Layer w8: R162.1@2461.38,640 2390,640 2317.2,712.8 2317.2,1561.01 2520.49,1764.3 2520.79,1764 2762,1764 2814.31,1816.31 U24.101@2814.31,1871.65
EVM1_ADC_SDO0: R171.1 U24.84 | length 1365.7
  Bottom Layer w8: R171.1@2461.38,940 2455,940 2398.6,996.4 2398.6,1199.21 2527.09,1327.7 2553.7,1327.7 2555,1329 2688,1329 3148.95,1789.95 U24.84@3148.95,1871.65
EVM1_ADC_SDO1: R172.1 U24.77 | length 1412.7
  Bottom Layer w8: R172.1@2461.38,990 2414.3,1037.08 2414.3,1192.71 2533.59,1312 2705,1312 3102,1709 3187,1709 3286.75,1808.75 U24.77@3286.75,1871.65
EVM1_ADC_SDO2: R173.1 U24.76 | length 1359.4
  Bottom Layer w8: R173.1@2461.38,1040 2430,1071.38 2430,1186.2 2538.5,1294.7 2545,1294.7 ; 2545,1296.3 2711.5,1296.3 3096.7,1681.5 3185.5,1681.5 3306.43,1802.43 U24.76@3306.43,1871.65
EVM1_ADC_SDO3: R175.1 U24.75 | length 1314.4
  Bottom Layer w8: R175.1@2461.38,1090 2461.38,1195.38 2545,1279 2717,1279 3048,1610 3174,1610 3326.12,1762.12 U24.75@3326.12,1871.65
EVM1_DVDD: C83.1 J3.50 J13.1 R252.2 | length 1547.7
  Top Layer w20: J13.1@1725,3182 1807,3182
  Top Layer w30: C83.1@2652.5,1058.94 v1(2710,1058.94)
  Bottom Layer w10: v1(2580,1060) 2600.16,1039.84 J3.50@2652.5,1039.84 2709.84,1039.84 2710,1040 v1(2710,1058.94)
  Bottom Layer w20: J13.1@1725,3182 2532,3182 2732,3382 2732,3543
  other v1: 2710,1010
EVM1_ID_PWR: C75.2 C84.1 C128.2 C133.2 C155.2 J3.59 R246.2 U21.1 U21.8 U26.6 U27.5 U29.6 | length 4909.5
  Top Layer w20: v1(2964,1134) 3224.76,1134 v2(3357,1266.24)
  Top Layer w30: v2(2370,3826) 2370,3821.93 2470.93,3721 v2(2537.76,3721) 2537.76,3677.76 2505,3645 v1(2505,3550) 2505,3445 2055,2995 2055,2655 2185,2525 2185,1884.73 2374.73,1695 2675,1695 2910,1460 2910,1153.44 C84.1@2895.5,1138.94 2959.06,1138.94 v1(2964,1134)
  Bottom Layer w10: J3.59@2895.5,1138.34 2896.5,1137.34 2960.66,1137.34 v1(2964,1134)
  Bottom Layer w12: 3331.5,1008.5 3356.39,983.61 U21.1@3356.39,937.81
  Bottom Layer w15: U27.5@2369.65,3736.59 2369.65,3789.27 C133.2@2371.38,3791 2370,3792.38 v2(2370,3826) ; v1(2505,3550) 2572.62,3550 C155.2@2575,3552.38 2575.27,3552.65 U29.6@2627.41,3552.65 ; v2(2537.76,3721) 2536.38,3722.38 C128.2@2575,3722.38 2580.27,3727.65 U26.6@2626.41,3727.65 ; R246.2@3200,1008.5 3331.5,1008.5 3356.39,1033.39 U21.8@3356.39,1164.19 C75.2@3356.38,1230 3356.38,1265.62 v2(3357,1266.24)
EVM1_ID_SCL: J3.58 U21.6 | length 850.8
  Bottom Layer w8: J3.58@2652.5,1118.64 2688,1118.64 2689.65,1120.29 2695,1120.29 2722.3,1147.59 2722.3,1236.3 2771.7,1285.7 3224.47,1285.7 3304.51,1205.65 U21.6@3304.51,1161.21
EVM1_ID_SDA: J3.56 U21.5 | length 823.7
  Bottom Layer w8: J3.56@2652.5,1098.94 2688,1098.94 2689.65,1097.29 2704.53,1097.29 2738,1130.77 2738,1229.8 2778.2,1270 3207.64,1270 3278.92,1198.72 U21.5@3278.92,1161.21
EVM1_REG_5V5: C82.1 J3.1 J12.1 | length 155.4
  Top Layer w20: C82.1@2895.5,586.14 2898.36,589 2946.09,589 v1(2968.04,567.04)
  Bottom Layer w10: J3.1@2895.5,567.04 v1(2968.04,567.04)
  other v1: 2920,510 2970,510 2970,610
EVM2_1.25V_1: U30.4 U30.5 | length 56.4
  Bottom Layer w15: v2(5475,2837) 5475.41,2837.41 U30.4@5505.65,2837.41 U30.5@5505.65,2863
EVM2_1.25V_2: U32.4 | length 40.7
  Bottom Layer w15: U32.4@5521.41,3096.35 5521.41,3070.59 v2(5532,3060)
EVM2_ADC_CONVST: R190.1 U25.121 | length 1372.6
  Bottom Layer w8: R190.1@5956.38,2051.8 5904.3,1999.72 5904.3,1893.5 6023.5,1774.3 6449.3,1774.3 6743.73,2068.73 U25.121@6925.65,2068.73
EVM2_ADC_CSN: R193.1 U25.126 | length 1144.9
  Top Layer w8: v2(5893,2075) 5900,2075 5915,2090 v2(6650,2090)
  Bottom Layer w8: v2(5893,2075) 5918.8,2100.8 R193.1@5956.38,2100.8 ; v2(6650,2090) 6727.16,2167.16 U25.126@6925.65,2167.16
EVM2_ADC_RESETN: R186.1 U25.125 | length 1195.5
  Bottom Layer w8: R186.1@5955.38,1953.8 5955.38,1909.62 6055,1810 6440,1810 6777.47,2147.47 U25.125@6925.65,2147.47
EVM2_ADC_RVS: R200.1 U25.129 | length 1151
  Top Layer w8: v2(5885,2225) 5915,2195 v2(6530,2195)
  Bottom Layer w8: v2(5885,2225) 5885,2227 5905.8,2247.8 R200.1@5959.38,2247.8 ; v2(6530,2195) 6561.21,2226.21 U25.129@6925.65,2226.21
EVM2_ADC_SCLK: R195.1 R199.1 U25.127 | length 1133.8
  Top Layer w8: v2(5910.1,2149.8) 5917.6,2142.3 v2(6580,2142.3)
  Bottom Layer w8: v2(5910.1,2149.8) R195.1@5957.38,2149.8 5957.38,2197.8 R199.1@5958.38,2198.8 ; v2(6580,2142.3) 6624.54,2186.84 U25.127@6925.65,2186.84
EVM2_ADC_SDI: R189.1 U25.124 | length 1308.6
  Bottom Layer w8: R189.1@5955.38,2002.8 5920,1967.42 5920,1900 6030,1790 6442.2,1790 6779.99,2127.79 U25.124@6925.65,2127.79
EVM2_ADC_SDO0: R210.1 U25.130 | length 1139
  Top Layer w8: v2(5892.4,2280) 5947.4,2225 v2(6505,2225)
  Bottom Layer w8: v2(5892.4,2280) 5910.2,2297.8 R210.1@5959.38,2297.8 ; v2(6505,2225) 6512.2,2225 6533.1,2245.9 U25.130@6925.65,2245.9
EVM2_ADC_SDO1: R212.1 U25.131 | length 1137.3
  Top Layer w8: v2(5900,2334.6) 5983.3,2251.3 6561.3,2251.3 v2(6585,2275)
  Bottom Layer w8: v2(5900,2334.6) 5912.2,2346.8 R212.1@5958.38,2346.8 ; v2(6585,2275) 6594.42,2265.58 U25.131@6925.65,2265.58
EVM2_ADC_SDO2: R213.1 U25.132 | length 1128.4
  Top Layer w8: v2(5910.5,2385) 6020.5,2275 v2(6490,2275)
  Bottom Layer w8: v2(5910.5,2385) 5921.3,2395.8 R213.1@5958.38,2395.8 ; v2(6490,2275) 6492,2275 6515.7,2298.7 6602.3,2298.7 6615.73,2285.27 U25.132@6925.65,2285.27
EVM2_ADC_SDO3: R215.1 U25.134 | length 1156.4
  Top Layer w8: v2(5895.2,2444.8) 6031.06,2308.94 6631.91,2308.94 v2(6647.61,2324.64)
  Bottom Layer w8: v2(5895.2,2444.8) R215.1@5958.38,2444.8 ; v2(6647.61,2324.64) U25.134@6925.65,2324.64
EVM2_DVDD: C89.1 J17.1 J18.50 R258.2 | length 3438.6
  Top Layer w20: v1(5355,1891) 5355,2430 5485,2560 ; v2(5403,2909) 5403,2642 5485,2560 ; v4(6226,2406) 6224.1,2404.1 C89.1@6156,2404.1 6105.9,2404.1 5950,2560 5485,2560
  Bottom Layer w10: J18.50@6156,2404.7 v4@6224.7,2404.7
  Bottom Layer w15: v2(5403,2909) R258.2@5403,2951 ; v4@6224.7,2404.7 v4(6226,2406)
  Bottom Layer w30: v1(5355,1891) 5355,1850 6050,1155 J17.1@6050,765
EVM2_ID_PWR: C90.1 C220.2 C223.2 C224.2 C226.2 J18.59 R251.2 U28.1 U28.8 U30.6 U31.5 U32.6 | length 2979.6
  Top Layer w15: 5419,2982 v2(5508,2982)
  Top Layer w20: v1(5205,2445) 5205,2768 5419,2982 5422.2,2985.2 5504.8,2985.2 5571.62,3052.02 v2(5571.62,3187.38) ; v2(5508,2982) 5508,2956 5566,2898 5768.24,2898 v2(5793,2873.24) 6071.24,2595 6193.65,2595 6309.35,2479.3 C90.1@6408.75,2479.3 6410.7,2481.25 v4(6410.7,2550)
  Bottom Layer w10: J18.59@6399,2503.2 6399,2538.3 v4(6410.7,2550)
  Bottom Layer w15: R251.2@5140,2221.5 5200.62,2221.5 5202.11,2220 ; U28.8@5202.11,2088.81 5202.11,2220 ; v1(5205,2445) 5206.38,2443.62 C220.2@5206.38,2395 5202.11,2390.74 U28.1@5202.11,2315.19 5202.11,2220 ; U30.6@5505.65,2888.59 5505.65,2909.15 5518.38,2921.88 C223.2@5518.38,2941 5518.38,2971.62 v2(5508,2982) ; v2(5571.62,3187.38) C226.2@5571.62,3154 5572.59,3153.03 U32.6@5572.59,3096.35 ; v2(5793,2873.24) 5793.62,2872.62 C224.2@5793.62,2907 5794.35,2907.73 U31.5@5794.35,2956.41
EVM2_ID_SCL: J18.58 U28.6 | length 1133.3
  Bottom Layer w8: U28.6@5253.3,2088.81 5253.3,2126.32 5254.59,2127.62 5254.59,2155.53 5617.36,2518.3 6064.85,2518.3 6098,2485.15 6118.85,2485.15 6120.5,2483.5 J18.58@6156,2483.5
EVM2_ID_SDA: J18.56 U28.5 | length 1101.3
  Bottom Layer w8: U28.5@5278.89,2088.81 5278.89,2126.32 5277.59,2127.62 5277.59,2156.32 5616.57,2495.3 6055.32,2495.3 6088.47,2462.15 6118.85,2462.15 6120.5,2463.8 J18.56@6156,2463.8
EVM2_REG_5V5: C87.1 J18.1 | length 159.9
  Top Layer w20: C87.1@6399,1951 6474,1951 v4(6475,1950)
  Bottom Layer w10: J18.1@6399,1931.9 6456.9,1931.9 v4(6475,1950)
FB: C42.2 R220.1 R223.2 U3.6 | length 397.9
  Bottom Layer w20: R223.2@5618,3375 C42.2@5618,3464 R220.1@5618,3555 5756,3555 5767,3566 U3.6@5767,3630.37
FSTS0_LED: R123.1 R209.1 U25.75 | length 1455.4
  Top Layer w8: v2(7982.5,1527.5) 8045,1465 8510,1465 8641.5,1333.5 v2(8641.5,1261.5)
  Bottom Layer w8: U25.75@7646.12,1761.65 7646.12,1688.88 7742.7,1592.3 7917.7,1592.3 v2(7982.5,1527.5) R123.1@7982.5,1432.62 7996.43,1418.69 ; v2(8641.5,1261.5) R209.1@8695,1261.5
FSTS1_LED: R124.2 R264.1 U25.76 | length 1610.6
  Top Layer w8: v2(7930,1525) 8010,1445 8505,1445 8615,1335 8615,1117.99 v2(8641.5,1091.5)
  Bottom Layer w8: U25.76@7626.43,1761.65 7626.43,1683.57 7735,1575 7879,1575 7929.5,1524.5 R124.2@7929.5,1432.62 ; v2(8641.5,1091.5) R264.1@8695,1091.5
FSTS2_LED: R125.1 R266.1 U25.77 | length 1762.2
  Top Layer w8: v2(7880,1525) 7980,1425 8490,1425 8595,1320 8595,992.99 v2(8641.5,946.5)
  Bottom Layer w8: U25.77@7606.75,1761.65 7606.75,1673.25 7720.7,1559.3 7845.7,1559.3 v2(7880,1525) 7878.5,1523.5 R125.1@7878.5,1432.62 ; v2(8641.5,946.5) R266.1@8695,946.5
FSTS3_LED: R126.2 R265.1 U25.78 | length 1920.2
  Top Layer w8: v2(7830,1525) 7950,1405 8485,1405 8575,1315 8575,866.5 v2(8641.5,800)
  Bottom Layer w8: U25.78@7587.06,1761.65 7587.06,1662.94 7725,1525 v2(7830,1525) 7827.5,1522.5 R126.2@7827.5,1432.62 ; v2(8641.5,800) R265.1@8695,800
GND: C8.2 C11.1 C13.2 C14.2 C15.2 C16.2 C25.1 C27.2 C28.2 C29.2 C30.2 C39.2 C40.2 C41.2 C43.2 C45.2 C46.2 C47.2 C48.1 C86.2 C87.2 C89.2 C90.2 C91.2 C156.2 C157.2 C158.2 C159.2 C160.2 C161.2 C162.2 C163.2 C164.2 C165.2 C166.2 C167.2 C168.2 C169.2 C170.2 C171.2 C172.2 C173.2 C174.2 C175.2 C176.2 C177.2 C178.2 C179.2 C180.2 C181.2 C182.2 C183.2 C184.2 C185.2 C186.2 C187.2 C188.2 C189.2 C190.2 C191.2 C193.2 C194.2 C195.2 C196.2 C198.2 C199.2 C200.2 C201.2 C202.2 C203.2 C204.2 C205.2 C206.2 C207.2 C208.2 C209.2 C210.2 C211.2 C212.2 C213.2 C215.2 C216.2 C217.2 C218.2 C220.1 C222.1 C223.1 C224.1 C225.2 C226.1 C227.2 C229.1 C236.2 D7.1 D8.1 D14.1 J1.1 J1.2 J2.1 J2.2 J2.43 J2.44 J2.45 J2.46 J5.1 J18.60 J18.MP1 J18.MP2 J18.MP3 J18.MP4 J19.5 J21.2 Q2.2 Q4.2 Q7.2 R77.1 R78.1 R79.1 R80.1 R81.1 R82.1 R83.1 R84.1 R183.1 R185.1 R187.1 R217.2 R224.1 R225.1 R256.1 R257.1 R259.1 TP26.1 TP27.1 TP28.1 TP29.1 U1.4 U3.4 U3.8 U5.2 U5.6 U5.8 U6.2 U9.2 U9.8 U11.2 U12.9 U12.15 U13.7 U13.21 U25.9 U25.17 U25.26 U25.34 U25.56 U25.65 U25.81 U25.89 U25.100 U25.106 U25.118 U25.128 U25.137 U28.2 U28.3 U28.4 U30.2 U32.2 U35.4 Y2.2 | length 11147.8
  Top Layer w10: v3(5126.25,3179.76) 5151.84,3154.17 U13.7@5217.78,3154.17
  Top Layer w15: v1(5138.25,2919.3) R77.1@5138.25,2964.14 ; v1(5188.25,2919.3) R78.1@5188.25,2964.14 ; R80.1@5345.87,3155.76 5347.11,3157 v1(5383,3157) ; R81.1@5345.87,3205.76 v1(5383,3205.76) ; R82.1@5345.87,3255.76 5383,3255.76 ; v2(5624,2856) v2@5625,2855 ; v2(6805,2018) 6805,2006 6837.5,1973.5 C185.2@6865,1973.5 6873.94,1982.44 C176.2@6927.64,1982.44 ; v2(6887,1675.5) C163.2@6887,1714.38 ; v2(6938,1675.5) C162.2@6938,1714.38 ; v2(7020,2217.5) C164.2@7020,2256.38 ; v2(7025.5,1932.5) C177.2@7025.5,1971.38 ; C168.2@7027,2135.62 v2(7027,2174.5) ; v2(7070,2217.5) C157.2@7070,2256.38 ; v2(7075.5,1932.5) C188.2@7075.5,1971.38 ; C174.2@7076,2135.62 v2(7076,2174.5) ; v2(7125.5,1932.5) C189.2@7125.5,1971.38 ; C171.2@7127,2144.5 v2(7127,2183.37) ; v2(7147.5,1855) C201.2@7186.38,1855 ; v2(7147.5,1905) C213.2@7186.38,1905 ; C212.2@7186.38,1955 v2(7186.38,1993.88) ; C173.2@7291,1904.62 v2(7291,1943.5) ; C167.2@7340,1903.62 v2(7340,1942.5) ; C199.2@7478.62,1850 v2(7517.5,1850) ; C210.2@7478.62,1900 v2(7517.5,1900) ; C211.2@7478.62,1950 v2(7517.5,1950) ; C195.2@7565,2098.62 v2(7565,2137.5) ; v2(7565.5,2275) C172.2@7604.38,2275 ; v2(7566.5,2226) C166.2@7605.38,2226 ; v2(7615,1863.5) C159.2@7615,1902.38 ; C183.2@7615,2098.62 v2(7615,2137.5) ; v2(7665,1862.5) C158.2@7665,1901.38 ; C196.2@7665,2098.62 v2(7665,2137.5)
  Top Layer w20: v1(4773.71,3329.76) C45.2@4829.32,3329.76 ; v1@4782.64,3050.37 C47.2@4838.25,3050.37 ; v1(4834.15,3249.76) C46.2@4889.75,3249.76 ; v1@4935,3768 v1(4935,3769) ; C48.1@5091.25,3406.26 v1(5091.25,3457.3) ; R84.1@5151.25,3398.39 v1(5151.25,3445) ; R78.1@5188.25,2964.14 5189.24,2965.13 R79.1@5238.76,2965.13 ; R83.1@5201.25,3398.39 v1(5201.25,3449.42) ; v1(5837.35,451.88) C28.2@5783.85,451.88 ; v1(5839.32,771.88) C29.2@5790.82,771.88 5790.82,693.85 C30.2@5788.85,691.88 5763.24,666.28 5763.24,665.85 5757.35,659.96 U6.2@5757.35,517.75 5757.35,478.81 5783.85,452.31 C28.2@5783.85,451.88 ; v1(5842.35,371.88) C27.2@5785.82,371.88 5783.85,373.85 C28.2@5783.85,451.88 ; C41.2@5868.5,3629 5869,3628.5 v1(5869,3550) ; C89.2@6156,2484.1 v4(6228.9,2484.1) ; C87.2@6399,2031 v4@6468,2031 ; C13.2@6399.4,320.04 C13.2@6397.43,322.01 ; C90.2@6408.75,2399.3 v4(6476.7,2399.3) ; v1(6437.9,720.04) C15.2@6389.4,720.04 6392.43,717.01 C16.2@6392.43,640.04 6392.43,617.43 6370.93,595.93 U11.2@6370.93,465.9 6370.93,426.96 6397.43,400.46 C14.2@6397.43,400.04 ; v1(6450.93,400.04) C14.2@6397.43,400.04 ; v1(6453.96,322.01) C13.2@6397.43,322.01 ; v1@6584.87,58.37 v1(6585.27,57.97) ; v2(6836,1665) C161.2@6836,1702.5 ; C184.2@6875,2426.5 6882.87,2418.62 C178.2@6930,2418.62 C179.2@7020,2418.62 v2(7020,2456) ; C191.2@7070,2418.62 v2(7070,2456) ; C190.2@7120,2418.62 v2(7120,2456) ; v2(7159,1666) 7161,1666 7177.01,1682.01 C207.2@7177.01,1730 7184.88,1737.87 C200.2@7184.88,1780 ; v2(7167,2505) C203.2@7207.76,2505 7204.11,2508.65 C202.2@7204.11,2587.35 7204.11,2634.48 C208.2@7196.24,2642.35 ; v2(7170.38,2405) C216.2@7207.76,2405 ; v2(7170.38,2455) C215.2@7207.76,2455 ; v2(7316,2535) 7331.38,2519.62 C169.2@7331.38,2504 C175.2@7331.38,2452 ; C170.2@7322.5,2394 7322.5,2353.5 v2(7323,2353.99) ; C198.2@7478.62,1775 7478.62,1727.87 C206.2@7486.5,1720 7515.5,1691 v2(7538,1691) ; v2(7493.62,2362.62) C218.2@7493.62,2400 C217.2@7493.62,2450 ; C205.2@7493.62,2500 7493.62,2530.38 v2(7493,2531) 7493.62,2531.62 C204.2@7493.62,2585 7493.62,2632.13 C209.2@7501.5,2640 ; v2(7560,2379) C193.2@7560,2416.38 ; v2(7610,2379) C194.2@7610,2416.38 ; v2(7660,2379) C181.2@7660,2416.38 7661.06,2417.44 C180.2@7737.64,2417.44 7784.76,2417.44 C186.2@7792.64,2409.57 ; C196.2@7665,2098.62 C182.2@7740,2098.62 7787.13,2098.62 C187.2@7795,2106.5 ; v1(7795,2555) 7797.62,2557.62 C156.2@7797.62,2592 7797.62,2642 C165.2@7798.62,2643 7798.62,2689.13 C160.2@7806.5,2697 ; R217.2@8025.5,2239 8094,2239 v1(8095,2240) ; R183.1@8026.5,2493 v4(8081,2493) ; C13.2@6397.43,322.01 C14.2@6397.43,400.04
  Bottom Layer w10: J18.60@6156,2503.2 6209.8,2503.2 v4(6228.9,2484.1) ; v2(6805,2018) 6808.35,2018 6816.68,2009.68 U25.118@6925.65,2009.68 ; U25.128@6925.65,2206.53 7009.03,2206.53 v2(7020,2217.5) ; U25.137@6925.65,2383.69 6964.69,2383.69 7020,2439 v2(7020,2456) ; U25.106@7035.88,1761.65 7035.88,1820.88 7045,1830 ; U25.100@7153.99,1761.65 7153.99,1671.01 v2(7159,1666) ; U25.9@7153.99,2592.35 7153.99,2518.01 v2(7167,2505) ; U25.17@7311.47,2592.35 7311.47,2539.53 v2(7316,2535) ; U25.89@7370.53,1761.65 7370.53,1814.47 7370,1815 7380,1825 v1(7380,1870) ; U25.26@7488.64,2592.35 7488.64,2535.36 v2(7493,2531) ; U25.81@7528.01,1761.65 7528.01,1700.99 v2(7538,1691) ; v2(7640,2004) 7687.93,2004 7706.7,1985.23 7706.7,1983.81 7720.2,1970.31 U25.65@7756.35,1970.31 ; v1(7645,2660) 7646.12,2661.12 U25.34@7646.12,2592.35 ; v2(7665,2137.5) 7674.97,2147.47 U25.56@7756.35,2147.47
  Bottom Layer w15: J21.2@4980,2260 5023.62,2260 C222.1@5080,2203.62 ; U28.2@5227.7,2315.19 U28.3@5253.3,2315.19 5253.3,2394.67 C220.1@5253.62,2395 5253.62,2443.62 v1(5255,2445) ; 5263.32,2315.19 U28.4@5278.89,2315.19 ; R259.1@5407,3074 v2(5407,3112) ; v2(5463,3111) 5464,3110 C227.2@5464,3067.62 ; v1(5485,2730) R256.1@5534,2730 ; v1(5490,2785) C225.2@5538.38,2785 ; v2(5523.62,3186.62) 5524.38,3186.62 C226.1@5524.38,3154 ; v2(5547,2982) U32.2@5547,3015.65 ; C223.1@5565.62,2941 5604,2941 v2(5606,2943) ; U30.2@5586.35,2863 5616,2863 5623,2856 v2(5624,2856) ; 7045,1830 7070,1855 v2(7147.5,1855)
  Bottom Layer w20: C236.2@4436.93,725 v1(4575,725) ; U35.4@4495.28,968 4548,968 v1(4549,969) ; v1(4566,2070.98) 4566,2108.98 U9.8@4568.01,2110.98 ; v1(4566.01,1541.99) 4566.01,1579.98 U5.8@4568.02,1581.99 ; U5.6@4568.02,1681.99 4569.01,1681 v1(4638,1681) ; U5.2@4568.02,1881.99 4644.63,1881.99 C11.1@4646.01,1883.37 4679.63,1883.37 4681.01,1881.99 v1(4683.51,1881.99) ; U9.2@4568.01,2410.98 4644.62,2410.98 C25.1@4646,2412.36 4679.62,2412.36 4681,2410.98 v1(4683.5,2410.98) ; U12.15@4571.01,2698 4647.62,2698 C43.2@4649,2696.62 v1(4687.62,2696.62) ; U12.9@4571.01,2998 4574,3000.99 v1(4574,3043) ; C229.1@4613.62,1118 v1(4613.62,1161.62) ; v1(4798,488) 4939,488 4940,487 5081,487 v1(5082,486) ; U1.4@4896.21,3592.92 4896.21,3637.21 v1(4897,3638) ; v1(4925,4015) 4926,4014 TP28.1@5067,4014 5068,4013 v1(5209,4013) ; D7.1@4934.5,3816 4934.5,3769.5 v1(4935,3769) ; TP27.1@4937,487 4937,617 v1(4938,618) ; v1(5069,3883) 5070,3884 TP28.1@5070,4014 ; R225.1@5621,3284 v1(5677,3284) ; v1(5745,2860) 5746.38,2861.38 C224.1@5746.38,2907 ; v1(5762,3349) R224.1@5762,3409 ; v2(5788.41,3056.59) Q7.2@5788.41,3095.5 ; R257.1@5841,2960.38 5877.38,2960.38 v2(5876.76,2961) ; 5867,3759.65 U3.4@5867,3630.37 5867,3548 v1(5869,3550) ; C39.2@6153,3791.96 v1(6153,3847) ; C40.2@6277,3792.96 v1(6277,3848) ; J18.MP1@6277.5,1884.9 6279,1886.4 v1(6279,1968) 6277.5,1966.5 J18.MP2@6277.5,2092.4 J18.MP3@6277.5,2342.4 J18.MP4@6277.5,2549.9 ; v1(6585.27,57.97) 6585.46,57.97 Q2.2@6585.46,108.13 ; v1(7160.78,399.03) 7161.03,398.79 Q4.2@7198.38,398.79 ; v1(7275,4085) 7276,4085 D8.1@7276,4021.5 ; v1(7480,570) 7481.5,571.5 D14.1@7530,571.5 ; C86.2@8053.62,2180 v1(8095,2180) ; Y2.2@8073.46,2031.69 v1(8126.69,2031.69) ; v1(8074,1773) R187.1@8118.5,1773 ; R185.1@8179.5,1516 8223,1516 v1(8224,1515) ; v1(8240,4002) 8241,4001 8382,4001 8383,4000 v1(8524,4000) ; v1(8384,3870) 8385,3871 TP29.1@8385,4001 ; v1(8386,315) 8385,314 TP26.1@8385,185 ; TP26.1@8388,184 8387,185 TP26.1@8385,185 ; v1(8530,183) 8524,177 TP26.1@8385,177 TP26.1@8385,185
  other v1: 4783.64,3043.37 6373,3844 6470,3846 6581,3850 6373,3976 6470,3978 6581,3982 6374,4085 6471,4087 6582,4091
  other v2: 5388,3425 5393,3480
  other v3: 5126.25,3127.6 5074.08,3179.76 5178.41,3179.76 5126.25,3231.93
  other v4: 6470,2029
  other v5: 5788,3828 5868,3828 5948,3828 5788,3928 5868,3928 5948,3928 5788,4028 5868,4028 5948,4028
GNDA_ADC: J2.34
GPIO_2: J2.22 R134.1 | length 94.7
  Bottom Layer w8: R134.1@7428.5,1383.38 7428.5,1296.5 J2.22@7434,1291
GPIO_3: J2.21 R133.2 | length 210.8
  Bottom Layer w8: J2.21@7434,1191 7478.5,1235.5 R133.2@7478.5,1383.38
GPIO_4: J2.18 R130.1 | length 96.1
  Bottom Layer w8: R130.1@7627.5,1384.38 7627.5,1297.5 J2.18@7634,1291
GPIO_5: J2.17 R129.2 | length 211.4
  Bottom Layer w8: J2.17@7634,1191 7677.5,1234.5 R129.2@7677.5,1384.38
GPIO_8: J1.35 R33.2 | length 130.6
  Bottom Layer w8: J1.35@6734,3091 6790,3035 R33.2@6790,2983.62
GPIO_9: J1.33 R31.2 | length 130.6
  Bottom Layer w8: J1.33@6834,3091 6890,3035 R31.2@6890,2983.62
GPIO_10: J1.31 R29.2 | length 130.6
  Bottom Layer w8: J1.31@6934,3091 6990,3035 R29.2@6990,2983.62
GPIO_11: J1.32 R30.1 | length 251.3
  Bottom Layer w8: J1.32@6934,3191 6990,3135 6990,3070 7040,3020 R30.1@7040,2983.62
GPIO_15: J2.24 R136.1 | length 93.2
  Bottom Layer w8: R136.1@7329.5,1382.38 7329.5,1295.5 J2.24@7334,1291
GPIO_22: J1.19 R17.2 | length 130.6
  Bottom Layer w8: J1.19@7534,3091 7590,3035 R17.2@7590,2983.62
GPIO_23: J1.13 R11.2 | length 130.6
  Bottom Layer w8: J1.13@7834,3091 7890,3035 R11.2@7890,2983.62
GPIO_26: J1.14 R12.1 | length 251.3
  Bottom Layer w8: J1.14@7834,3191 7890,3135 7890,3075 7940,3025 R12.1@7940,2983.62
GPIO_27: J1.17 R15.2 | length 130.6
  Bottom Layer w8: J1.17@7634,3091 7690,3035 R15.2@7690,2983.62
GPIO_30: J2.11 R123.2 | length 214.5
  Bottom Layer w8: J2.11@7934,1191 7982.5,1239.5 R123.2@7982.5,1385.38
GPIO_31: J2.13 R125.2 | length 212.8
  Bottom Layer w8: J2.13@7834,1191 7878.5,1235.5 R125.2@7878.5,1385.38
GPIO_32: J1.25 R23.2 | length 130.6
  Bottom Layer w8: J1.25@7234,3091 7290,3035 R23.2@7290,2983.62
GPIO_33: J1.24 R22.1 | length 251.3
  Bottom Layer w8: J1.24@7334,3191 7390,3135 7390,3075 7440,3025 R22.1@7440,2983.62
GPIO_34: J1.5 R3.2 | length 130.6
  Bottom Layer w8: J1.5@8234,3091 8290,3035 R3.2@8290,2983.62
GPIO_35: J1.6 R4.1 | length 251.3
  Bottom Layer w8: J1.6@8234,3191 8234,3186 8285,3135 8285,3075 8340,3020 R4.1@8340,2983.62
GPIO_36: J1.23 R21.2 | length 130.6
  Bottom Layer w8: J1.23@7334,3091 7390,3035 R21.2@7390,2983.62
GPIO_37: J1.22 R20.1 | length 251.3
  Bottom Layer w8: J1.22@7434,3191 7490,3135 7490,3075 7540,3025 R20.1@7540,2983.62
GPIO_38: J1.3 R1.2 | length 130.6
  Bottom Layer w8: J1.3@8334,3091 8390,3035 R1.2@8390,2983.62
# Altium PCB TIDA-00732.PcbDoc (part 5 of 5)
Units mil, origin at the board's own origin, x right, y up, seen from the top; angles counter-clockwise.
Board outline 8994.78 x 4186 mil, 6 copper layers (Top Layer, GND1, PWR1, PWR2, GND2, Bottom Layer), stack 97.668 mil thick; 693 components, 463 nets, 2087 pads, 616 vias.

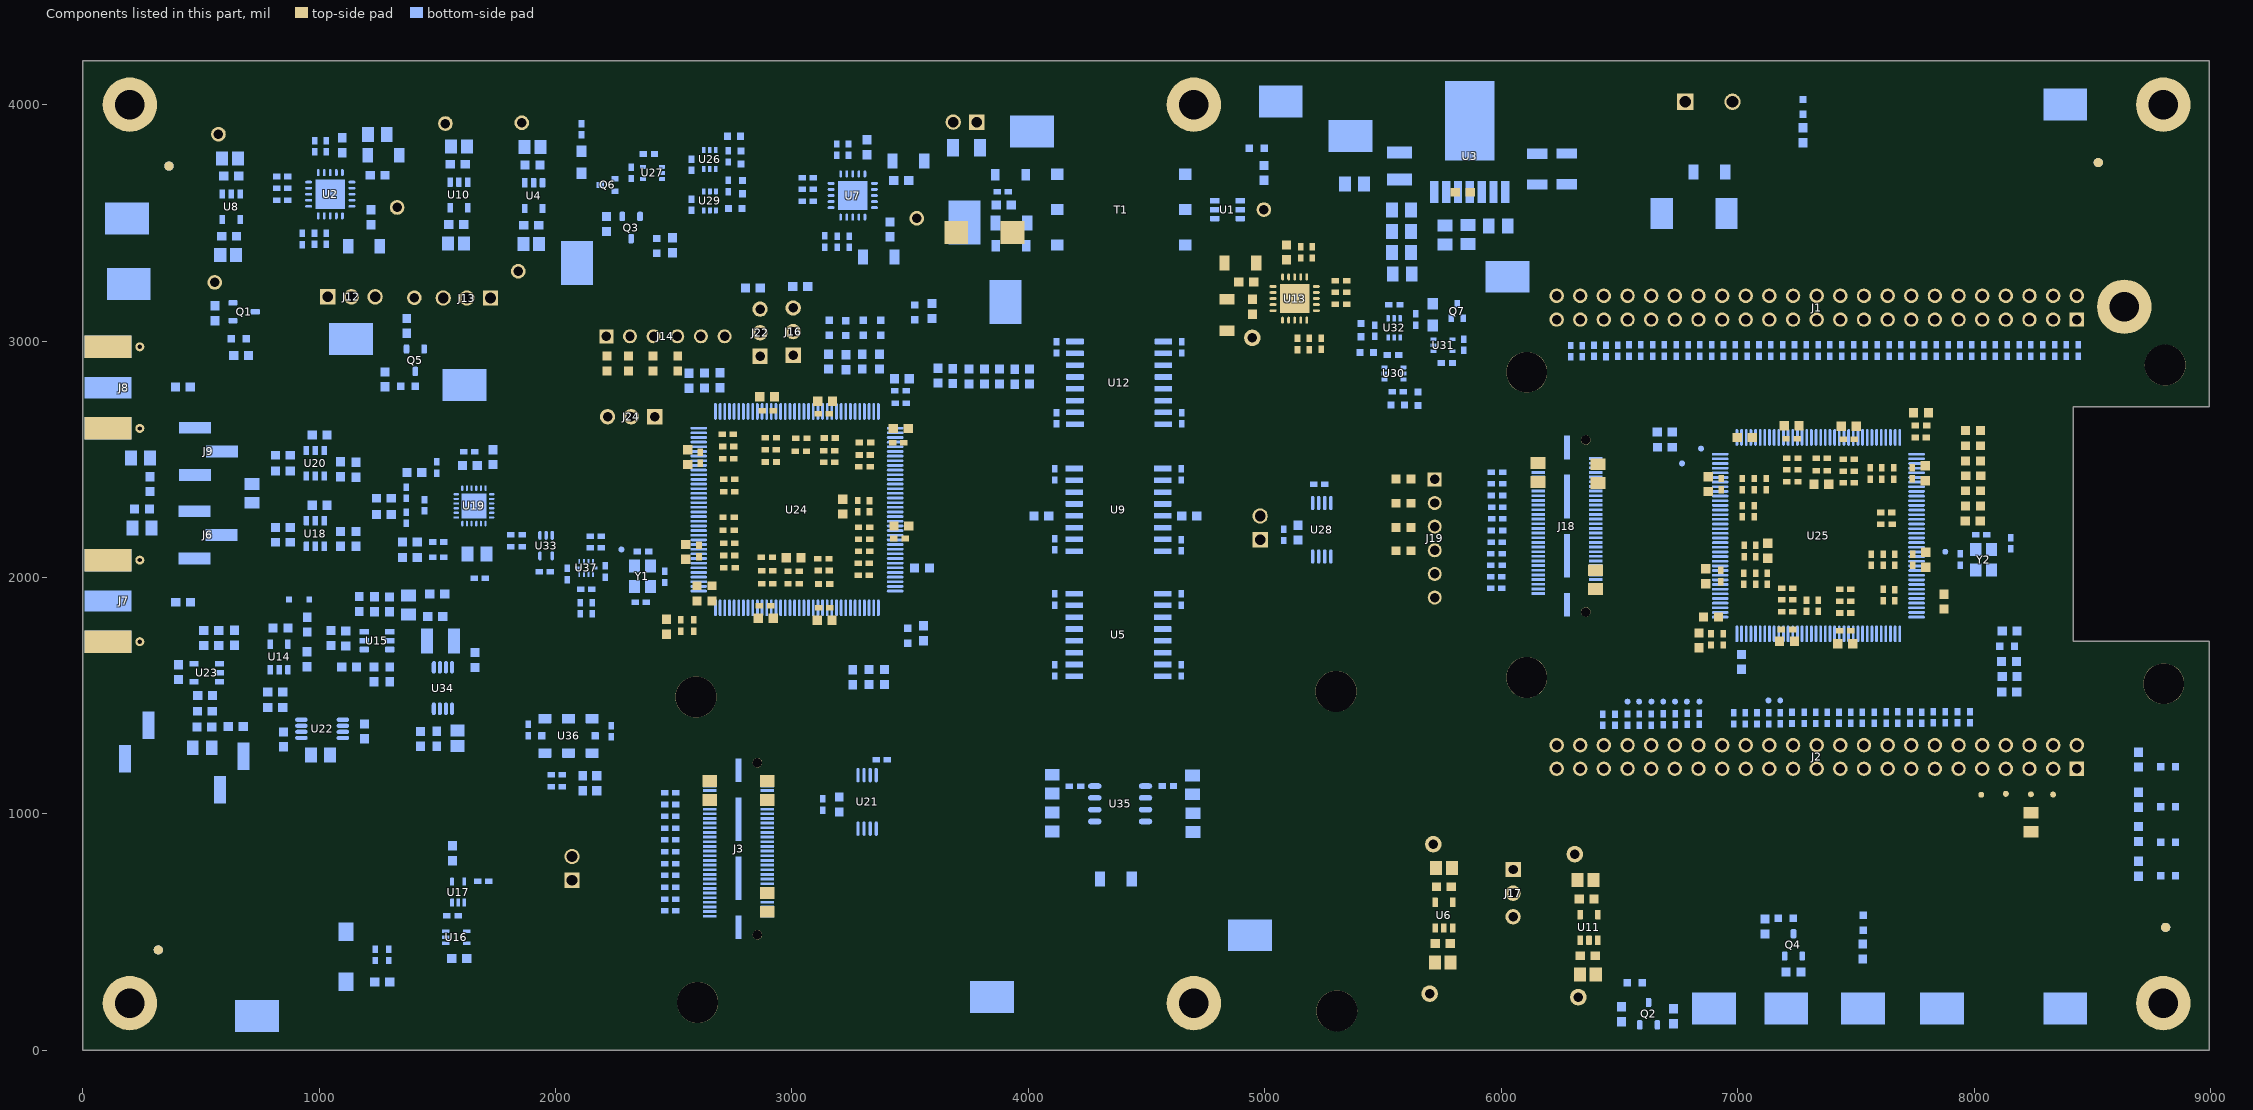
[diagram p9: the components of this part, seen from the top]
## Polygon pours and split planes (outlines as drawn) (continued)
LDO_IN_ISO on Bottom Layer "Top Layer-No Net" (solid, pour order 131): 1132.1,3663.62 1235.1,3663.62 1239.1,3667.62 1239.1,3985.62 1227.1,3997.62 1139.1,3997.62 1129.1,3987.62 1129.1,3732.62 1124.1,3727.62 1092.1,3727.62 1088.1,3723.62 1088.1,3698.62 1091.1,3695.62 1120.1,3695.62 1123.1,3692.62 1123.1,3667.62 1127.1,3663.62
LDO_IN_ISO on Bottom Layer "Top Layer-No Net" (solid, pour order 125): 1576.5,3848 1576.5,3728 1566.5,3718 1566.5,3658 1561.5,3653 1546.5,3653 1536.5,3653 1506.5,3653 1486.5,3673 1486.5,3948 1501.5,3963 1571.5,3963 1576.5,3958
LDO_IN_ISO on Bottom Layer "Top Layer-No Net" (solid, pour order 123): 1892.5,3845 1892.5,3725 1882.5,3715 1882.5,3655 1877.5,3650 1862.5,3650 1852.5,3650 1822.5,3650 1802.5,3670 1802.5,3945 1817.5,3960 1887.5,3960 1892.5,3955
1P8V_ISO1 on Bottom Layer "Top Layer-No Net" (solid, pour order 120): 1571.5,3588 1571.5,3268 1561.5,3258 1491.5,3258 1471.5,3278 1471.5,3478 1526.52,3533.02 1526.52,3578.02 1536.5,3588
A1P8V_ISO on Bottom Layer "Top Layer-No Net" (solid, pour order 110): 608.5,3538 608.5,3218 598.5,3208 528.5,3208 508.5,3228 508.5,3428 563.52,3483.02 563.52,3528.02 573.5,3538
1P2V_ISO on Bottom Layer "Top Layer-No Net" (solid, pour order 102): 1887.5,3585 1887.5,3265 1877.5,3255 1807.5,3255 1787.5,3275 1787.5,3475 1842.52,3530.02 1842.52,3575.02 1852.5,3585
NetC2_1 on Bottom Layer "Top Layer-No Net" (solid, pour order 133): 3750,3962 3750,3739 3650,3639 3650,3373 3691,3332 3849,3332 3883,3366 3883,3726 3857,3752 3841,3768 3841,3958 3834,3965 3753,3965
LDO_IN_ISO on Bottom Layer "Top Layer-No Net" (solid, pour order 134): 3730,3974 3730,3780 3714,3764 3630,3764 3623,3771 3623,3777 3623,3871 3623,3910 3577,3956 502,3956 502,4068 518,4084 3716,4084 3730,4070
LDO_IN_ISO on Bottom Layer "Top Layer-No Net" (solid, pour order 99): 502,3978 502,3621 517,3606 522,3601 603,3601 608,3606 608,3609 608,3672 616,3680 616,3977 611,3982 506,3982 505,3981
LDO_IN_ISO on Bottom Layer "Top Layer-No Net" (solid, pour order 106): 3367.18,3823.46 3367.18,3977.18 3373,3983 3446,3983 3453,3976 3454.18,3974.82 3454.18,3662.46 3451.18,3659.46 3336.18,3659.46 3333.18,3662.46 3333.18,3687.48 3331.19,3689.47 3305.17,3689.47 3302.18,3692.46 3302.18,3723.46 3304.18,3725.46 3360.18,3725.46 3367.18,3732.46 3367.18,3823.46
NetC42_1 on Bottom Layer "Top Layer-No Net" (solid, pour order 95): 5737,3681 5737,3585 5730,3578 5687,3578 5664,3601 5579,3601 5570,3592 5570,3435 5559,3424 5514,3424 5499,3439 5499,3610 5488,3621 5397,3621 5388,3630 5388,3712 5399,3723 5726,3723 5737,3712
GND on Bottom Layer "Top Layer-No Net" (solid, pour order 101): 6838,3711 6838,4124 6816,4146 5510,4146 5500,4136 5500,3777 5520,3757 6639,3757 6726,3670 6825,3670 6838,3683
+12VDC_IN on Bottom Layer "Top Layer-No Net" (solid, pour order 104): 6893,4114 6893,3481 6907,3467 7055,3467 7067,3479 7067,4139 7057,4149 6902,4149 6893,4140
+12VDC on Bottom Layer "Top Layer-No Net" (solid, pour order 108): 5995,3471 5995,3432 6006,3421 6726,3421 6746,3441 6746,3616 6725,3637 6405,3637 6341,3701 6008,3701 5998,3691
3P3V_ISO on Bottom Layer "Top Layer-No Net" (solid, pour order 109): 3339,3574 3596,3574 3610,3560 3610,3495 3595,3480 3260,3480 3245,3495 3245,3537 3250,3542 3327.42,3542 3334.94,3549.52 3334.94,3571.94 3337,3574
AGND_ISO on Bottom Layer "Top Layer-No Net" (solid, pour order 115): 3120,3417 3315,3417 3323,3409 3323,3317 3311,3305 3077,3305 3052,3330 3052,3480 2979,3553 2979,3896 3330.21,3896 3345.72,3880.49 3345.72,3832.72 3340,3827 3333,3820 3208,3820 3078,3820 3065,3807 3060,3802 3060,3635 3060,3575 3068,3567 3119,3567 3148,3596 3197,3596 3198,3595 3198,3582 3196,3580 3156,3580 3135,3559 3105,3529 3105,3452 3105,3427 3115,3417
5VDC on Bottom Layer "Top Layer-No Net" (solid, pour order 169): 5365,3710 5365,3615 5365,3515 5340,3490 4962,3490 4946,3506 4946,3701 4950,3705 5360,3705 5365,3700
NetC62_1 on Bottom Layer "Top Layer-No Net" (solid, pour order 170): 1630,2552.84 1584.01,2552.84 1581.35,2550.18 1581.35,2378.65 1595,2365 1630,2365
NetC2_1 on Bottom Layer "PWR-No Net" (solid, remove dead copper, pour order 88): 3753,3965 3750,3962 3750,3961 3750,3739 3650,3639 3650,3502 3600,3452 3592,3444 3592,3395 3592,3344 3604,3332 3747,3332 3849,3332 3883,3366 3883,3726 3841,3768 3841,3958 3834,3965
EVM1_DVDD on Top Layer "Top Layer-No Net" (solid, pour order 94): 1675,3210 1695,3230 1705,3230 1780,3230 1833.54,3230 1870,3193.54 1870,3186.46 1870,2990 1870,2230 2040,2060 2040,1540 2385,1195 2500,1080 2700,1080 2740,1080 2750,1070 2750,1000 2740,990 2465,990 2370,1085 1960,1495 1960,1980 1675,2265 1675,2685 1675,3210 1680,3215
GND on Top Layer "Top Layer-No Net" (solid, remove dead copper, pour order 98): 4462,58 4462,4140 8890,4140 8940,4090 8940,2775 8905,2740 8415,2740 8390,2715 8390,1715 8410,1695 8940,1695 8960,1675 8960,85 8920,45 4475,45
EVM1_REG_5V5 on Top Layer "Top Layer-No Net" (solid, pour order 89): 970,3240 1077,3240 1087,3230 1087,2783 1940,1930 1940,1580 1940,1460 2740,660 2770,630 2914,630 2980,630 3000,610 3000,490 2990,480 2690,480 1830,1340 1830,1730 1830,1860 960,2730 960,3190 960,3230
AGND_ISO on Top Layer "Top Layer-No Net" (solid, pour order 154): 3017,2138 3017,1921 3022,1916 3050,1916 3058,1924 3054,1928 3054,2147 3019,2147 3017,2145
AGND_ISO on Top Layer "Top Layer-No Net" (solid, pour order 153): 3140,2102 3140,1953.85 3143,1950.85 3207.85,1950.85 3212,1955 3212,2090 3197,2105 3143,2105 3140,2102
AGND_ISO on Top Layer "Top Layer-No Net" (solid, pour order 152): 3295,2075 3254,2075 3250,2071 3250,1961 3255,1956 3291,1956 3297,1962 3297,2074 3296,2075
AGND_ISO on Top Layer "Top Layer-No Net" (solid, pour order 151): 3292,2234.65 3220.65,2234.65 3215,2229 3215,2104 3220,2099 3295,2099 3299,2103 3299,2229.65 3294,2234.65
AGND_ISO on Top Layer "Top Layer-No Net" (solid, pour order 150): 3315,2293 3194,2293 3189,2288 3189,2256 3194,2251 3381.06,2251 3387.53,2257.47 3387.53,2286.47 3382,2292
AGND_ISO on Top Layer "Top Layer-No Net" (solid, pour order 149): 3301,2596 3301,2455 3294,2448 3230,2448 3223,2455 3223,2599 3226,2602 3299,2602 3301,2600
AGND_ISO on Top Layer "Top Layer-No Net" (solid, pour order 148): 3168,2603 3168,2431 3172,2427 3197,2427 3203,2433 3203,2643 3198,2648 3160,2648 3156,2644 3156,2615 3168,2603
AGND_ISO on Top Layer "Top Layer-No Net" (solid, pour order 147): 3026,2652 2990,2652 2986,2648 2986,2493 2992,2487 3026,2487 3031,2492 3031,2648 3026,2653
AGND_ISO on Top Layer "Top Layer-No Net" (solid, pour order 146): 2903,2603 2903,2427 2898,2422 2854,2422 2849,2427 2849,2641 2849,2828 2865,2828 2903,2790 2903,2596
AGND_ISO on Top Layer "Top Layer-No Net" (solid, pour order 145): 2737,2617 2737,2482 2740,2479 2806,2479 2815,2488 2815,2621 2809,2627 2740,2627 2737,2624
AGND_ISO on Top Layer "Top Layer-No Net" (solid, pour order 143): 2741.62,2430 2741.62,2349 2743.62,2347 2812.62,2347 2816.62,2351 2816.62,2431 2812.62,2435 2744.62,2435 2741.62,2432
AGND_ISO on Top Layer "Top Layer-No Net" (solid, pour order 144): 2739,2267 2739,2186 2741,2184 2810,2184 2814,2188 2814,2268 2810,2272 2742,2272 2739,2269
AGND_ISO on Top Layer "Top Layer-No Net" (solid, pour order 142): 2739,2163 2809,2163 2818,2154 2818,2129 2813,2124 2785.35,2124 2776,2114.65 2776,1989 2770,1983 2749,1983 2742,1990 2742,2160 2745,2163
AGND_ISO on Top Layer "Top Layer-No Net" (solid, pour order 141): 2889,2100 2889,1765 2877,1753 2838,1753 2830,1761 2813,1778 2813,2081 2813,2101 2817,2105 2884,2105 2889,2100
GND on Top Layer "Top Layer-No Net" (solid, pour order 140): 5330,3262 5330,3270 5222,3378 5066,3378 5058,3386 5058,3467 5064,3473 5209,3473 5402,3280 5402,3059 5252,2909 5238,2895 5122,2895 5112,2895 5102,2905 5102,2975 5105,2978 5107,2980 5148,2980 5265,2980 5301,3016 5301,3072 5236,3137 5231,3142 5212,3142 5186,3142 5182,3146 5182,3160 5185,3163 5246,3163 5281,3128 5287,3122 5317,3122 5322,3122 5326,3126 5330,3130 5330,3140
5VDC on Top Layer "Top Layer-No Net" (solid, pour order 126): 5742.35,341.88 5742.35,461.88 5732.35,471.88 5732.35,531.88 5727.35,536.88 5712.35,536.88 5702.35,536.88 5672.35,536.88 5652.35,516.88 5652.35,241.88 5667.35,226.88 5737.35,226.88 5742.35,231.88
1P8V_1 on Top Layer "Top Layer-No Net" (solid, pour order 86): 5749.75,597.75 5749.75,933.25 5739,944 5676.01,944 5660.12,928.13 5659.89,697.61 5704.77,652.73 5704.77,607.73 5714.75,597.75
3P3V on Top Layer "Top Layer-No Net" (solid, pour order 130): 5046.25,3135.3 4914.25,3135.3 4906.25,3127.3 4906.25,2938.75 4910,2935 5010,2935 5016.25,2941.25 5016.25,3036.3 5027.25,3047.3 5111.25,3047.3 5133.25,3069.3 5133.25,3101.3 5129.25,3105.3 5053.25,3105.3 5051.25,3107.3 5051.25,3132.3 5048.25,3135.3
5VDC on Top Layer "Top Layer-No Net" (solid, pour order 129): 5081.25,3283.3 5081.25,3256.3 5053.25,3256.3 5051.25,3254.3 5051.25,3226.3 4926.25,3226.3 4926.25,3406.3 4931.25,3411.3 5026.25,3411.3 5031.25,3406.3 5031.25,3306.3 5051.25,3286.3 5078.25,3286.3
5VDC on Top Layer "Top Layer-No Net" (solid, pour order 127): 6355.93,290.04 6355.93,410.04 6345.93,420.04 6345.93,480.04 6340.93,485.04 6325.93,485.04 6315.93,485.04 6285.93,485.04 6265.93,465.04 6265.93,190.04 6280.93,175.04 6350.93,175.04 6355.93,180.04
1P2V on Top Layer "Top Layer-No Net" (solid, pour order 121): 6350.93,550.04 6350.93,870.04 6340.93,880.04 6270.93,880.04 6250.93,860.04 6250.93,660.04 6305.95,605.02 6305.95,560.02 6315.93,550.04
GND on Top Layer "Top Layer-No Net" (solid, pour order 155): 7463,1961 7463,1679 7469,1673 7545,1673 7550,1678 7550,1961 7538,1973 7464.35,1973 7463,1971.65
GND on Top Layer "Top Layer-No Net" (solid, pour order 156): 7679,1919 7599,1919 7595,1915 7595,1851 7600,1846 7681,1846 7685,1850 7685,1917 7683,1919
GND on Top Layer "Top Layer-No Net" (solid, pour order 157): 7669,2083 7811.37,2083 7816.79,2088.42 7816.79,2144.21 7809,2152 7546,2152 7538,2144 7538,2090 7545,2083
GND on Top Layer "Top Layer-No Net" (solid, pour order 158): 7620,2285 7620,2206 7616,2202 7554,2202 7545,2211 7545,2289 7552,2296 7618,2296 7620,2294
GND on Top Layer "Top Layer-No Net" (solid, pour order 159): 7548,2432 7810,2432 7814,2428 7814,2373 7809,2368 7548,2368 7544,2372 7544,2428 7548,2432
GND on Top Layer "Top Layer-No Net" (solid, pour order 160): 7478,2507 7478,2658 7483,2663 7524,2663 7526,2661 7526,2355 7517,2346 7488,2346 7479,2355
GND on Top Layer "Top Layer-No Net" (solid, pour order 161): 7347,2511 7347,2547 7344,2550 7303,2550 7297,2544 7297,2343 7302,2338 7342,2338 7346,2342
GND on Top Layer "Top Layer-No Net" (solid, pour order 162): 7216,2659 7216,2527 7224,2519 7224,2382 7220,2378 7166,2378 7160,2384 7160,2662 7164,2666 7213,2666 7216,2663
GND on Top Layer "Top Layer-No Net" (solid, pour order 163): 6920,2401.3 7132.3,2401.3 7139,2408 7139,2467 7133,2473 6854,2473 6849,2468 6849,2414 6860,2403 6861.7,2401.3 6918,2401.3
GND on Top Layer "Top Layer-No Net" (solid, pour order 164): 7083,2273 6999,2273 6996,2270 6996,2210 7001,2205 7084,2205 7086,2207 7086,2271 7084,2273
GND on Top Layer "Top Layer-No Net" (solid, pour order 165): 7002,2187 7145,2187 7153,2179 7153,2129.3 7145.7,2122 7001,2122 6996,2127 6996,2182 7001,2187
GND on Top Layer "Top Layer-No Net" (solid, pour order 166): 7137,1990 6951,1990 6942,1999 6847,1999 6825,2021 6812,2034 6799,2034 6791,2034 6786,2029 6786,1963 6797,1952 6833,1916 7086,1916 7129,1916 7140,1927 7140,1987 7137,1990
GND on Top Layer "Top Layer-No Net" (solid, pour order 167): 7203,1993 7203,1655 7190,1642 7136,1642 7125,1653 7125,1890.87 7160.79,1926.65 7160.79,1997.79 7169,2006 7198,2006 7203,2001
GND on Top Layer "Top Layer-No Net" (solid, pour order 168): 7275,1956 7275,1891 7278,1888 7355,1888 7358,1891 7358,1959 7355,1962 7278,1962 7275,1959
NetC2_1 on Top Layer "PWR-No Net" (solid, remove dead copper, pour order 91): 3670,3658 3750,3658 3756,3652 3756,3350 3740,3334 3738,3332 3720,3332 3604,3332 3592,3344 3592,3444 3600,3452 3643,3495 3643,3591 3643,3650 3651,3658
AGND_ISO on Top Layer "PWR-No Net" (solid, remove dead copper, pour order 93): 4083,3646 4083,3412 4075,3404 3886,3404 3878,3412 3878,3644 3887,3653 4076,3653 4083,3646
1P2V on PWR2 "Top Layer-No Net" (solid, pour order 118): 5900,525 8890,525 8940,575 8940,1655 8900,1695 8405,1695 8390,1710 8390,2705 8365,2730 7370,2730 7310,2670 7310,2135 7280,2105 5955,2105 5880,2030 5880,1325 5880,545
1P8V on PWR2 "Top Layer-No Net" (solid, pour order 116): 5525,575 5525,2390 5815,2680 5815,3250 5875,3310 8885,3310 8930,3265 8930,2780 8890,2740 7340,2740 7280,2680 7280,2140 7270,2130 5905,2130 5855,2080 5855,1325 5855,550 5830,525 5575,525 5570,530
5VDC on PWR2 "Top Layer-No Net" (solid, pour order 113): 4440.55,1009.52 4440.55,4045.55 4485,4090 5725,4090 8885,4090 8925,4050 8925,3570 8925,3395 8915,3385 8875,3345 6970,3345 5795,3345 5770,3320 5770,2660 5487,2377 5487,553 5540,500 8905,500 8945,460 8945,70 8905,30 4490,30 4440,80
1P2V_ISO on PWR2 "Top Layer-No Net" (solid, pour order 111): 4150,2130 4220,2130 4230,2140 4230,4045 4175,4100 1755,4100 1730,4075 1730,2800 1790,2740 2620,2740 2720,2640 2720,2146 2736,2130 4145,2130
5V_ISO on PWR2 "Top Layer-No Net" (solid, pour order 107): 4283.6,1109.52 4283.6,1451.4 4255,1480 1210,1480 1160,1530 1160,4075 1130,4105 70,4105 55,4090 55,65 70,50 4260,50 4280,70
1P8V_ISO on PWR2 "Top Layer-No Net" (solid, pour order 135): 1200,3290 1200,4085 1215,4100 1685,4100 1710,4075 1710,3775 1710,2770 1765,2715 2605,2715 2690,2630 2690,2125 2710,2105 4195,2105 4230,2070 4230,1560 4210,1540 1215,1540 1200,1555
3P3V_ISO on PWR1 "Top Layer-No Net" (solid, pour order 92): 4306.24,4088.76 4250,4145 105,4145 60,4100 60,105 115,50 4220,50 4312.3,142.3
VCCO_0 on PWR1 "Top Layer-No Net" (solid, pour order 105): 2275,2750 2345,2750 2355,2740 2355,2540 2365,2530 2670,2530 2710.39,2489.61 2710.39,2135.39 2675,2100 2500,2100 2485,2115 2485,2315 2475,2325 2320,2325 2280,2365 2265,2380 2265,2740 2265,2745 2270,2750
3P3V on PWR1 "Top Layer-No Net" (solid, pour order 136): 4462.17,172.83 4580,55 8920,55 8960,95 8960,1655 8930,1685 8410,1685 8390,1705 8390,2730 8400,2740 8925,2740 8950,2765 8950,4115 8915,4150 4595,4150 4462.17,4017.17
GND on GND1 "Top Layer-No Net" (solid, pour order 97): 4462,58 4462,4140 8890,4140 8940,4090 8940,2775 8905,2740 8415,2740 8385,2710 8385,1700 8390,1695 8940,1695 8960,1675 8960,85 8920,45 4475,45
AGND_ISO on GND1 "Top Layer-No Net" (solid, pour order 90): 4310,125 4310,4085 4250,4145 105,4145 60,4100 60,105 115,50 4235,50
GND on GND2 "Top Layer-No Net" (solid, pour order 96): 4463.57,4133.57 4470,4140 8890,4140 8940,4090 8940,2775 8905,2740 8415,2740 8385,2710 8385,1705 8395,1695 8960,1695 8960,85 8920,45 4475,45 4461.3,58.7
AGND_ISO on GND2 "Top Layer-No Net" (solid, pour order 87): 4310,140 4310,4070 4235,4145 90,4145 45,4100 45,105 100,50 4220,50

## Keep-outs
GND1:
  lines w20: 10,980 1710,980 1720,980 1755,1015 1755,2142.52 ; 10,3075 398,3075 783,2690 1775,2690 1810,2655 1810,2420
GND2:
  lines w20: 10,980 1720,980 1755,1015 1755,2142.52 ; 10,3075 398,3075 783,2690 1775,2690 1810,2655 1810,2420
Keep-Out Layer:
  lines w4: 8973,1011 8973,1710 8402,1710 8402,2720 8969,2720 8969,4168 35,4168 35,24 8973,24 8973,1012.78
  text ".Layer_Name" at -185.22,-1588.49 h60
Multi-Layer:
  circle w10: c2854,1216.74 r24.64
  circle w10: c6357.5,2581.6 r24.64
  circle w10: c6357.5,1853.6 r24.64
  circle w10: c2854,488.74 r24.64
  circle w10: c320,425 r53.15
  circle w10: c365,3740 r53.15
  circle w10: c8525,3755 r53.15
  circle w10: c8810,520 r53.15

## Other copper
Top Layer:
  text "TOP LAYER" at -186,-1570 h60
PWR1:
  text "PWR1" at -50,-1585 h40
GND1:
  text "GND1" at -25,-1575 h40
PWR2:
  text "PWR2" at -70,-1590 h40
GND2:
  text "GND2" at -45,-1575 h40
Bottom Layer:
  text "BOTTOM LAYER" at -185.22,-1588.49 h60
Multi-Layer:
  pour cut-out: 328.24,3795.02 419,3795.02 419,3681 326,3681 312,3681 312,3695 312,3794 312.99,3794.99
  pour cut-out: 283.24,480.02 374,480.02 374,366 281,366 267,366 267,380 267,479 267.99,479.99
  pour cut-out: 2817.24,1271.76 2908,1271.76 2908,1157.74 2815,1157.74 2801,1157.74 2801,1171.74 2801,1270.74 2801.99,1271.74
  pour cut-out: 2817.24,543.76 2908,543.76 2908,429.74 2815,429.74 2801,429.74 2801,443.74 2801,542.74 2801.99,543.74
  pour cut-out: 6320.74,1908.62 6411.5,1908.62 6411.5,1794.6 6318.5,1794.6 6304.5,1794.6 6304.5,1808.6 6304.5,1907.6 6305.49,1908.59
  pour cut-out: 6320.74,2636.62 6411.5,2636.62 6411.5,2522.6 6318.5,2522.6 6304.5,2522.6 6304.5,2536.6 6304.5,2635.6 6305.49,2636.59
  pour cut-out: 8773.24,575.02 8864,575.02 8864,461 8771,461 8757,461 8757,475 8757,574 8757.99,574.99
  pour cut-out: 8488.24,3810.02 8579,3810.02 8579,3696 8486,3696 8472,3696 8472,3710 8472,3809 8472.99,3809.99

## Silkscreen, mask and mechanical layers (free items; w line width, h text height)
Top Overlay:
  circle w10: c6288,466 r9.43
  circle w10: c5676,517 r7
  circle w10: c5075,3050 r7.07
  lines w6: 2564,2187 2586.5,2164.5 2586.5,2160 ; 2728,1994 2728,2011 ; 2779.47,2702 2779.47,2643.53 ; 2845,2123 2845,2133 2834,2122 2844,2122 2823,2143 2823,2265 2831,2265 2831.53,2264.47 2935.47,2264.47 2935.47,2182 ; 2979,2433 2980,2432 2980,2320 2979,2319 2864,2319 2863,2320 2863,2335 2863,2443 ; 3046,2140 3063,2140 3063,2263 2945,2263 2946,2262 2946,2245 2946,2135 ; 3135,2139 3072,2139 3072,2261 3183,2261 3183,2242 3182,2241 3182,2131 ; 3208,2610.5 3208,2614 3227,2633 3227,2647 ; 3210,2549 3238,2577 3238,2624 3255,2641 3255,2647 ; 3235,2083 3235,1976 3255,1956 ; 3241,2242 3382,2242 3388,2236 3388,1734 3266,1734 3266,1846 3266,1938 ; 3277.01,1926.99 3266,1938 ; 7180,2102 7163,2102 ; 7194,2346 7169,2346 7169,2215 7277,2215 7280,2218 7280,2343 ; 7224,1675 7224,1695 ; 7227,2342 7227,2369 ; 7316,2332 7296,2332 7290,2326 7288,2324 7288,2215 7396,2215 7401,2220 7401,2325 7393,2333 7380,2333 ; 7359,2333 7359,2352 ; 7416,2326.99 7416,2133 7535,2133 7535,2325 7534,2326 ; 7460,1652 7460,1680 ; 7461,2338 7461,2365 ; 7535,2016 7500,2016 ; 8259,1072 8279.5,1051.5 ; 2728,2011 2722,2005 2736,2005 2734,2005 2728,2011 ; 2779.47,2643.53 2790,2654.06 2790,2655 2789,2654 2769,2654 2779.47,2643.53 ; 2863,2443 2864.01,2443 2873.01,2434 2854,2434 2863,2443 ; 2946,2135 2946,2136 2954,2144 2937,2144 2946,2135 ; 3182,2131 3173,2140 3190,2140 3182,2132 3182,2131 ; 3266,1938 3266,1936 3275,1927 3255,1927 3266,1938 ; 7163,2102 7169,2096 7169,2108 7163,2102 ; 7224,1695 7226,1695 7232,1689 7218,1689 7224,1695 ; 7227,2369 7229,2369 7236,2362 7220,2362 7227,2369 ; 7359,2352 7361,2352 7366,2347 7354,2347 7359,2352 ; 7460,1680 7462,1680 7469,1673 7453,1673 7460,1680 ; 7461,2365 7462,2365 7470,2357 7453,2357 7461,2365 ; 7500,2016 7507,2009 7507,2023 7500,2016
  text "TOP OVERLAY" at -185.22,-1588.49 h50
Bottom Overlay:
  circle w10: c4564,1985 r8
  circle w10: c383,2277 r6.71
  circle w10: c388,2632 r6.71
  circle w10: c1824,3664 r6.71
  circle w10: c5681,2945 r7.21
  circle w10: c5571,2988 r5.39
  circle w10: c5620,2888.59 r7.24
  circle w10: c4747,3518 r7.62
  circle w10: c4574,2511 r8
  circle w10: c4196,2596 r8
  circle w10: c2595,3643 r3.61
  circle w10: c2630.22,3838 r5.22
  circle w10: c2489.9,3736.59 r9.31
  circle w10: c1507,3673 r6.71
  circle w10: c1101,3488 r8.06
  circle w10: c550,3619 r6.32
  circle w10: c1343,1770 r8.06
  circle w10: c617,1642 r7.62
  circle w10: c1143,1399 r6.32
  circle w10: c1649,621 r7.62
  circle w10: c1497,452 r7
  circle w10: c1566,1404 r6.32
  circle w10: c1705,2198 r4.59
  circle w10: c1026,2091 r8.25
  circle w10: c1025,2385 r11.05
  circle w10: c6845,2545 r18.03
  circle w10: c6764.43,2482.57 r18.03
  circle w10: c7878,2109 r18.03
  circle w10: c7129,1481 r18.03
  circle w10: c7179,1480 r18.03
  circle w10: c5172,2319 r8.54
  circle w10: c4495,1160 r7.28
  circle w10: c1934.1,2218 r7.25
  circle w10: c2158,1989 r2.24
  circle w10: c3312,3486 r9.06
  circle w10: c871,1571 r6.71
  lines w6: 1916,2098 1916,2196 ; 2007,2114 2007,2168 ; 2057,1917 2075,1935 2075,1937 ; 2212,2204 2212,2215 ; 2814,3599 2837,3599 ; 2824,3721 2849,3721 ; 5351,3035 5370,3035 ; 5602,2923 5634.64,2923 5639,2918.64 ; 5615,3205 5630,3190 5630,3155 ; 5744,1726 5687,1726 5687,1321 5828,1321 5828,1725 ; 5777,1725 5828,1725 ; 5970,1909 5899,1909 5893,1915 5893,2490 6042,2490 6042,1911 6006,1911 ; 6484,1456 6483.38,1455.38 6421.62,1455.38 6388.62,1455.38 6388.62,1340.38 6876,1340.38 6876,1456 ; 6686,1074 6686,1327 ; 7084,1160 7084,1310 7124,1350 ; 7174,1350 7181,1343 7181,1156 ; 2212,2215 2207,2210 2220,2210 2215,2215 2212,2215 ; 2837,3599 2837,3596 2833,3592 2833,3603 2837,3599 ; 2849,3721 2842,3714 2842,3728 2849,3721 ; 5370,3035 5370,3033 5362,3025 5362,3043 5370,3035 ; 5828,1725 5899,1725 6032,1858 6032,1897 ; 6032,1897 6031,1897 6021,1887 6042,1887 6032,1897 ; 6686,1327 6684,1327 6674,1317 6696,1317 6686,1327 ; 6555,964 6555,1074 6901,1074 6902,1075 6902,964 6555,964
  text "+" at 7120,4130 h30
  text "-" at 6650,4120 h30
  text "GND" at 5000,4110 h25
  text "GND" at 8330,4100 h25
  text "AGND_ISO" at 4105,4035 h25
  text "+12V" at 7325,3940 h25 r270
  text "+12V_IN" at 7100,3890 h30 r270
  text "5V" at 4985,3855 h25
  text "AGND_ISO" at 285,3665 h25
  text "1P2V_ISO" at 2465,3260 h25
  text "3P3V" at 3565,3210 h25
  text "1P2V_ISO" at 2200,3170 h25
  text "+12V" at 6075,3145 h25
  text "JTAG1" at 2500,3140 h25
  text "1" at 3090,3130 h25
  text "A1P8V_ISO" at 298,3114 h25
  text "A1P8V_ISO" at 595,3000 h25
  text "1P8V_ISO" at 1711,2911 h25
  text "0" at 3090,2910 h25
  text "5V_ISO" at 1180,2887 h25
  text "VIN+" at 290,2770 h25 r270
  text "1P8V_ISO" at 1480,2705 h25
  text "JTAG2" at 5730,2485 h25
  text "VIN-" at 295,1860 h25 r270
  text "TIDA-00732_E1" at 8385,720 h60
  text "3P3V" at 7578,627 h25
  text "RESET" at 1155,595 h25
  text "GND" at 4895,580 h25
  text "1P8V" at 7375,544 h25
  text "1P2V" at 6615,370 h25
  text "AGND_ISO" at 3940,60 h25
  text "1P8V" at 7245,54 h25
  text "GND" at 8426,50 h25
  text "1P2V" at 6952,47 h25
  text "3P3V" at 7583,47 h25
  text "5V DC" at 7922,42 h25
  text "AGND_ISO" at 830,20 h25
  text "BOTTOM OVERLAY" at -71,-1602 h50
Top Paste:
  text "TOP PASTE" at -185.22,-1588.49 h60
Bottom Paste:
  text "BOTTOM PASTE" at -185.22,-1588.49 h60
Top Solder:
  text "TOP SOLDER" at -185.22,-1588.49 h60
Bottom Solder:
  text "BOTTOM SOLDER" at -185.22,-1588.49 h60
Drill Guide:
  text ".Layer_Name" at -185.22,-1588.49 h60
M1 Board Outline:
  the board outline again, w8
M2 Board Dimensions:
  rectangle: -762.72,-1015.5 -637.72,-890.5
  rectangle: -637.72,-1140.5 -262.72,-1015.5
  lines w7: -762.72,-1015.5 237.28,-1015.5 ; -637.72,-1140.5 -637.72,-890.5 ; -512.72,-1140.5 -512.72,-890.5 ; -262.72,-1140.5 -262.72,-890.5 ; -12.72,-1140.5 -12.72,-890.5 ; -762.72,-1140.5 237.28,-1140.5 237.28,-890.5 -762.72,-890.5 -762.72,-1140.5
  lines w10: -762.72,-1205.5 -762.72,-1185.5 ; -702.72,-1215.5 -762.72,-1195.5 ; -702.72,-1175.5 -762.72,-1195.5 ; -538.64,-1195.5 -762.72,-1195.5 ; 13.2,-1195.5 237.28,-1195.5 ; 177.28,-1215.5 237.28,-1195.5 ; 177.28,-1175.5 237.28,-1195.5 ; 237.28,-1205.5 237.28,-1185.5
  text "1000 (mil)" at -528.64,-1231.49 h60
M3 3D STEP Top:
  text ".Layer_Name" at -185.22,-1588.49 h60
M4 3D STEP Bottom:
  text ".Layer_Name" at -185.22,-1588.49 h60
M5 Assembly Top:
  circle w10: c6335,448 r6.32
  circle w10: c8433,3093 r15.23
  circle w10: c8436,1194 r19.31
  circle w10: c5720,500 r4.24
  lines w6: 2893,2117 2893,2134 ; 3006,2118 3006,2135 ; 3131,2114 3131,2131 ; 7217,1983 7217,2002 ; 7229,2345 7229,2368 ; 7355,2343 7355,2365 ; 7474,2346 7474,2366 ; 8164,1022 8164,1035 8213,1084 8219,1084 ; 2893,2134 2899,2128 2899,2127 2886,2127 2893,2134 ; 3006,2135 2999,2128 3012,2128 3012,2129 3006,2135 ; 3131,2131 3124,2124 3137,2124 3137,2125 3131,2131 ; 7217,2002 7218,2002 7223,1997 7212,1997 7217,2002 ; 7229,2368 7231,2368 7237,2362 7223,2362 7229,2368 ; 7355,2365 7357,2365 7363,2359 7349,2359 7355,2365 ; 7474,2366 7475,2366 7481,2360 7468,2360 7474,2366
  lines w10: -1054.22,-1660.17 5545.78,-1660.17 ; -1054.22,-1456.83 5547.78,-1456.83 ; -1054.22,-1253.5 -1054.22,-1863.5 2950.78,-1863.5 5547.78,-1863.5 5547.78,-1253.5 -1053.72,-1253.5 -1053.72,-1863.5 521.78,-1863.5 ; 1410.78,-1863.5 1410.78,-1253.5 ; 2677.78,-1456.83 2677.78,-1253.5 ; 3517.78,-1456.83 3517.78,-1253.5 ; 4139.78,-1870 4139.78,-1667.17
  text "TP17" at 4901,2906 h25
  text "TP31" at 8140,967 h25 r90
  text "TP15" at 8044,963 h25 r90
  text "TP30" at 8349,960 h25 r90
  text "L1" at 8220,956 h25
  text "TP25" at 8179,922 h25 r90
  text "TP9" at 5773,859 h25
  text "TP4" at 6371,816 h25
  text "TP10" at 5652,152 h25
  text "TP5" at 6293,132 h25
  text "COMPONENTS MARKED 'DNP' SHOULD NOT BE POPULATED." at 391.28,-1048.5 h25
  text "ASSEMBLY VARIANT:" at 390.78,-1164 h25
  text ".VariantName" at 1426.78,-1164 h25
  text "E1" at 3113,-1379 h25
  text "PCB VIEWED FROM TOP SIDE" at -990.72,-1385.67 h25
  text "BOARD #:" at 1485.78,-1385.67 h25
  text "TIDA-00732" at 2031.28,-1385.67 h25
  text "REV:" at 2875.78,-1385.67 h25
  text "SVN REV:" at 3713.78,-1385.67 h25
  text "ASSEMBLY TOP" at -179,-1583 h25
  text "IGNORE ->" at -990.72,-1588.49 h25
  text "PLOT NAME =" at -990.72,-1794.34 h25
  text ".plot_File_Name" at -185.22,-1794.34 h25
  text "GENERATED    :" at 1487.78,-1794.34 h25
  text "02/10/2015" at 2357.28,-1794.34 h25
  text "12:12:36 PM" at 3086.28,-1794.34 h25
  text "TEXAS INSTRUMENTS" at 4350.78,-1794.34 h25
M6 Assembly Bottom:
  circle w10: c1719,3183 r18.38
  circle w10: c1237,3189 r18.38
  circle w10: c4195.61,2649.38 r14.13
  circle w10: c4568.01,2460.98 r15.21
  circle w10: c4568.02,1931.99 r13.59
  circle w10: c1516.13,451.73 r6.08
  circle w10: c1613.13,609.73 r4.12
  circle w10: c599,1634.02 r8.6
  circle w10: c866,1591 r6.32
  circle w10: c497,2282 r6.32
  circle w10: c499,2633 r7.28
  circle w10: c619,3089 r9.06
  circle w10: c592,3647 r9.85
  circle w10: c1555,3696 r9.06
  circle w10: c1871,3693 r6.71
  circle w10: c1370,2983 r7.28
  circle w10: c2469,3736.59 r3.96
  circle w10: c3788,3927 r12.65
  circle w10: c5691,2957 r6.08
  circle w10: c5839,3067 r6.32
  circle w10: c6017,3630.37 r15.82
  circle w10: c4980,2160 r10.05
  circle w10: c5714,2421 r23.85
  circle w10: c7274,384 r7.21
  circle w10: c6661,90 r8.6
  circle w10: c2208,3018 r17.89
  circle w10: c2070,725 r20.62
  circle w10: c2678,2634 r6.32
  circle w10: c6997.65,2524 r6.32
  lines w6: 2657,2651.17 2657,1924.17 3385.17,1924.17 3385.17,2651 2657.17,2651 ; 4237,2492.68 4603.02,2492.68 4604.86,2490.84 4604.86,2081.13 4158.69,2081.13 4158.69,2492.68 4247.14,2492.68 ; 4237.01,1963.68 4603.03,1963.68 4604.87,1961.85 4604.87,1552.13 4158.7,1552.13 4158.7,1963.68 4247.15,1963.68 ; 4240,3029.69 4606.02,3029.69 4607.86,3027.86 4607.86,2618.14 4161.69,2618.14 4161.69,3029.69 4250.14,3029.69 ; 6616.2,3458.29 6722.5,3458.29 ; 6616.2,3619.71 6722.5,3619.71 ; 6909.5,3458.29 7011.87,3458.29 7029.58,3476.01 7029.58,3602.19 7012.06,3619.71 6909.5,3619.71 ; 6976.65,2541.17 6976.65,1814.17 7704.83,1814.17 7704.83,2541 6976.83,2541 ; 5663,3578 5663,4116 6079,4116 6079,3578 6046,3578 5663,3578
  lines w10: -1054.72,-1457.33 5547.28,-1457.33 ; -1052.72,-1660.67 5547.28,-1660.67 ; 353.28,-1870.5 353.28,-1667.67 ; 975.28,-1457.33 975.28,-1254 ; 1815.28,-1457.33 1815.28,-1254 ; 3082.28,-1864 3082.28,-1254 ; 3971.28,-1864 5546.78,-1864 5546.78,-1254 -1054.72,-1254 -1054.72,-1864 1542.28,-1864 5547.28,-1864 5547.28,-1254
  lines w30: 6616.2,3458.29 6616.2,3619.71
  text "TP8" at 1894,3983 h25
  text "TP14" at 1576,3980 h25
  text "TP13" at 613,3938 h25
  text "TP1" at 1362,3628 h25
  text "TP6" at 3564,3584 h25
  text "TP2" at 5032,3544 h25
  text "D2" at 6834,3533 h25
  text "TP7" at 1779,3278 h25
  text "TP12" at 1441,3246 h25
  text "TP11" at 496,3235 h25
  text "TP34" at 6844,2570 h25
  text "TP33" at 6813,2410 h25
  text "U24" at 3014,2305 h25
  text "U25" at 7403,2164 h25
  text "TP48" at 2263,2145 h25 r270
  text "TP49" at 7863,2132 h25 r270
  text "TP50" at 7115,1510 h25 r270
  text "TP19" at 6669,1508 h25 r270
  text "TP24" at 6720,1504 h25 r270
  text "TP22" at 6517,1502 h25 r270
  text "TP20" at 6775,1502 h25 r270
  text "TP51" at 7165,1502 h25 r270
  text "TP18" at 6575,1500 h25 r270
  text "TP23" at 6625,1500 h25 r270
  text "TP21" at 6825,1499 h25 r270
  text "COMPONENTS MARKED 'DNP' SHOULD NOT BE POPULATED." at 5339.78,-1048 h25
  text ".VariantName" at 4295.78,-1164 h25
  text "ASSEMBLY VARIANT:" at 5334.78,-1164 h25
  text "SVN REV:" at 779.28,-1386.17 h25
  text "REV:" at 1617.28,-1386.17 h25
  text "TIDA-00312" at 2461.78,-1386.17 h25
  text "BOARD #:" at 3007.28,-1386.17 h25
  text "PCB VIEWED FROM BOTTOM SIDE" at 5483.78,-1386.17 h25
  text "E1" at 1479,-1399 h25
  text "ASSEMBLY BOTTOM" at 1124,-1581 h25
  text "IGNORE ->" at 1785.63,-1588.49 h25
  text "TEXAS INSTRUMENTS" at 142.28,-1794.84 h25
  text "12:12:36 PM" at 1406.78,-1794.84 h25
  text "02/10/2015" at 2135.78,-1794.84 h25
  text "GENERATED    :" at 3005.28,-1794.84 h25
  text ".plot_File_Name" at 4678.28,-1794.84 h25
  text "PLOT NAME =" at 5483.78,-1794.84 h25
M9 Title Sheet:
  drawing of 54 lines, arcs and shapes, not listed
  text "1" at -22.38,7306.5 h70
  text "2" at 2473.28,7306.5 h70
  text "3" at 4962.62,7306.5 h70
  text "4" at 7469.29,7306.5 h70
  text "5" at 9968.28,7306.5 h70
  text "6" at 12473.28,7306.5 h70
  text "A" at -1178.72,6163.5 h70
  text "A" at 13621.28,6163.5 h70
  text "B" at -1178.72,3783.5 h70
  text "B" at 13621.28,3783.5 h70
  text "C" at -1178.72,1408.5 h70
  text "C" at 13621.28,1408.5 h70
  text ".PRJ_Title" at 10631.28,-585.83 h70
  text "DESIGNED FOR:" at 10581.28,-753.5 h45
  text ".PRJ_Customer" at 10631.28,-893.5 h70
  text "D" at -1178.72,-961.5 h70
  text "D" at 13621.28,-961.5 h70
  text "FILE NAME:" at 10581.28,-1053.5 h45
  text ".PCB_File_Name_No_Path" at 10631.28,-1173.5 h70
  text "Texas Instruments (TI) and/or its licensors do not warrant the accuracy or completeness of this specification" at 5611.78,-1335.34 h45
  text "ENGINEER:" at 10581.28,-1343.5 h45
  text "LAYOUT BY:" at 12086.28,-1343.5 h45
  text "or any information contained therein. TI and/or its licensors do not warrant that this design will meet" at 5566.79,-1448 h45
  text ".PRJ_Engineer" at 10631.28,-1498.49 h70
  text ".PCB_Layout" at 12136.78,-1498.49 h70
  text "the specifications, will be suitable for your application or fit for any particular purpose, or will operate in" at 5566.79,-1560.67 h45
  text "ALTIUM DESIGNER VERSION:" at 12086.28,-1653.5 h45
  text "an implementation. TI and/or its licensors do not warrant that the design is production worthy. You should" at 5566.79,-1673.33 h45
  text "completely validate and test your design implementation to confirm the system functionality for your application." at 5611.78,-1786 h45
  text ".print_Scale" at 10631.28,-1786.83 h70
  text ".Application_BuildNumber" at 12136.78,-1786.83 h70
  text "1" at -22.38,-1993.5 h70
  text "2" at 2473.28,-1993.5 h70
  text "3" at 4962.62,-1993.5 h70
  text "4" at 7469.29,-1993.5 h70
  text "5" at 9968.28,-1993.5 h70
  text "6" at 12473.28,-1993.5 h70
M10 Fab Notes:
  drawing of 228 lines, arcs and shapes, not listed
  text "DESIGN INFORMATION" at 11618.8,6080 h60
  text "(REFER ALSO ARRAY/PANEL PROFILING INFORMATION)" at 11257.24,5918.29 h60
  text "BOARD SIZE" at 10571.24,5914 h60
  text "106.32mm" at 11719,5790 h60
  text "X" at 11539.24,5786.18 h60
  text "228.47MM" at 10974,5780 h60
  text "Number of Layers :" at 10974.24,5589 h60
  text "6" at 12069.05,5579 h60
  text "MIN. TRACK WIDTH:" at 10974.24,5450 h60
  text "MIL" at 12225.24,5450 h60
  text "8" at 12046.54,5448.78 h60
  text "7.7" at 12005,5320 h60
  text "MIN. CLEARANCE:" at 10974.24,5318 h60
  text "MIL" at 12225.24,5318 h60
  text "19.685" at 11880,5190 h60
  text "MIN. VIA PAD SIZE:" at 10974.24,5186 h60
  text "MIL" at 12225.24,5186 h60
  text "5.90 MIL" at 11669.24,5044.29 h60
  text "MINIMUM ANNULAR RING" at 10645.01,5040.01 h60
  text "EXTERNAL" at 12482,5040 h60
  text "PER" at 10845.01,4922 h60
  text "IPC-D-275 CLASS 2 LEVEL C" at 11065.01,4922 h60
  text "MIL, HOLES" at 12553.24,4809.71 h60
  text "+/-" at 12160.78,4809 h60
  text "+/-" at 13014.78,4809 h60
  text "REGISTRATION TOLERANCES:" at 10645.01,4804 h60
  text "METAL" at 11844.78,4804 h60
  text "5" at 12420.98,4804 h60
  text "3" at 13253.98,4804 h60
  text "MIL" at 13370.24,4804 h60
  text "MATERIAL:" at 10570.24,4594.54 h60
  text "FR-4 High Tg" at 11556.68,4454.21 h60
  text "FR-408" at 10991.24,4445.64 h60
  text "OTHER" at 12479.24,4445.64 h60
  text "X" at 10835,4438 h60
  text "63 MIL (1.6mm) +/-10%" at 11311.34,4282.92 h60
  text "THICKNESS:" at 10645.01,4278.64 h60
  text "X" at 11183.18,4278.64 h60
  text "OTHER" at 12596.24,4278.64 h60
  text "TOLERANCE:" at 10645.01,4120.64 h60
  text "X" at 11484.31,4120.64 h60
  text "ANSI IPC-6012 TYPE 3 CLASS 2" at 11671.26,4120.64 h60
  text "OTHER +/-" at 11671.24,3964.64 h60
  text "BOW & TWIST:" at 10645.01,3807.64 h60
  text "X" at 11484.31,3807.64 h60
  text "ANSI IPC-6012 TYPE 3 CLASS 2" at 11671.26,3807.64 h60
  text "OTHER +/-" at 11671.24,3649.13 h60
  text "COPPER THICKNESS (FINISHED):" at 10570.24,3513.64 h60
  text "1.4MIL (1oz)" at 11450.24,3360.92 h60
  text "2MIL (1.4oz)" at 12217.24,3360.92 h60
  text "2.8MIL (2oz)" at 12944.24,3360.92 h60
  text "OUTER:" at 10927.24,3356.64 h60
  text "X" at 11321.78,3356 h60
  text "1.4MIL (1oz)" at 11450.24,3203.92 h60
  text "2.8MIL (2oz)" at 12217.24,3203.92 h60
  text "N/A" at 12943.78,3204.29 h60
  text "INNER SIGNAL:" at 10638.16,3199.64 h60
  text "X" at 11321.78,3196 h60
  text "DRILLING:" at 10570.24,3060.64 h60
  text "REFERENCE:" at 10645.01,2943.64 h60
  text "X" at 11293.24,2943.64 h60
  text "AS SHOWN" at 11480.24,2943.64 h60
  text "X" at 12194.24,2943.64 h60
  text "NC_DRILL FILES" at 12331.24,2943.64 h60
  text "PTH MIN COPPER THICKNESS:" at 10645.01,2785.64 h60
  text "X" at 11995.24,2785.64 h60
  text "1MIL" at 12132.24,2785.64 h60
  text "OTHER" at 12629.24,2785.64 h60
  text "BOARD FINISH:" at 10570.24,2626.64 h60
  text "SILKSCREEN:" at 10725.46,2508.64 h60
  text "X" at 11674.24,2508.64 h60
  text "TOP" at 11800.24,2508.64 h60
  text "X" at 12184.24,2508.64 h60
  text "BOTTOM" at 12311.24,2508.64 h60
  text "SILKSCREEN COLOR:" at 10725.46,2341.64 h60
  text "X" at 11673.2,2341.64 h60
  text "WHITE" at 11800.24,2341.64 h60
  text "OTHER" at 12311.24,2341.64 h60
  text "SOLDER RESIST COLOR:" at 10725.46,2171.64 h60
  text "X" at 11293.2,2012.44 h60
  text "GREEN" at 11420.24,2012.44 h60
  text "BLUE" at 12011.24,2012.44 h60
  text "OTHER" at 12549.24,2012.44 h60
  text "IMMERSION GOLD (ENIG)" at 11631.24,1823.92 h60
  text "ENEPIG" at 12968.78,1820.64 h60
  text "SURFACE FINISH:" at 10570.24,1819.64 h60
  text "X" at 11444.29,1819.64 h60
  text "IMM. TIN/SILVER OR EQUIV" at 10899.78,1662.64 h60
  text "OTHER" at 12331.24,1662.64 h60
  text "ARRAY/PANEL:" at 10570.24,1483.64 h60
  text "CUT AND TRIM PER MECH LAYER 1" at 11631.24,1479.35 h60
  text "N.C. ROUTE" at 11631.24,1327.64 h60
  text "X" at 12310.24,1327.64 h60
  text "V. SCORE" at 12497.24,1327.64 h60
  text "CERTIFICATION:" at 10570.24,1190.64 h60
  text "MATERIALS AND WORKMANSHIP FOR ALL PCBS" at 11295.24,1190.64 h60
  text "TO MEET OR EXCEED THE REQUIREMENTS OF:" at 11295.24,1092.64 h60
  text "X" at 10921.74,956.14 h60
  text "ANSI IPC-A-600F CLASS ->" at 11060.74,956.14 h60
  text "X" at 12699.8,956.14 h60
  text "2" at 12818.74,956.14 h60
  text "1" at 12503.74,954.64 h60
  text "3" at 13172.74,954.64 h60
  text "X" at 10923.8,796.64 h60
  text "UL 94V-0" at 11060.74,796.64 h60
  text "X" at 11735.8,796.64 h60
  text "RoHS" at 11872.74,796.64 h60
  text "OTHER" at 12517.14,796.64 h60
  text "PER ORDER" at 12914.2,796.64 h60
  text "ADDITIONAL REQUIREMENTS:" at 10570.24,655.64 h60
  text "VIA TENTING:" at 11787.78,655 h60
  text "X" at 12554.07,655.12 h60
  text "YES" at 12337.45,645.92 h60
  text "NO" at 12702.25,640.69 h60
  text "MICROSECTION:" at 10645.01,540.64 h60
  text "YES" at 11550.74,540.64 h60
  text "IMPEDANCE CONTROL:" at 11813.78,531 h60
  text "YES" at 12797.78,530 h60
  text "X" at 13339.78,523 h60
  text "NO" at 13173.25,512.69 h60
  text "REQUIRED" at 12412.24,384.5 h60
  text "BARE BOARD ELEC. TEST:" at 10645.01,381.64 h60
  text "NONE" at 11950.74,381.64 h60
  text "X" at 12285.24,381.64 h60
  text "PER ORDER" at 13004.24,381.64 h60
  text "MANUFACTURER'S UL:" at 10645.01,224.64 h60
  text "RAIL" at 11810.74,220.35 h60
  text "METAL" at 12302.55,220.35 h60
  text "X" at 12677.78,220 h60
  text "SILK" at 12814.24,220.35 h60
M11 Gerber Information:
  lines w10: -1054.22,-1660.17 5545.78,-1660.17 ; -1054.22,-1456.83 5547.78,-1456.83 ; -1054.22,-1253.5 -1054.22,-1863.5 2950.78,-1863.5 5547.78,-1863.5 5547.78,-1253.5 -1053.72,-1253.5 -1053.72,-1863.5 521.78,-1863.5 ; 1410.78,-1863.5 1410.78,-1253.5 ; 2677.78,-1456.83 2677.78,-1253.5 ; 3517.78,-1456.83 3517.78,-1253.5 ; 4139.78,-1870 4139.78,-1667.17
  text "E1" at 3169,-1381 h40
  text "ALL ARTWORK VIEWED FROM TOP SIDE" at -990.72,-1385.67 h60
  text "BOARD #:" at 1485.78,-1385.67 h60
  text "TIDA-00732" at 2031.28,-1385.67 h60
  text "REV:" at 2875.78,-1385.67 h60
  text "SVN REV:" at 3713.78,-1385.67 h60
  text "LAYER NAME =" at -990.72,-1588.49 h60
  text "PLOT NAME =" at -990.72,-1794.34 h60
  text ".plot_File_Name" at -185.22,-1794.34 h60
  text "GENERATED    :" at 1487.78,-1794.34 h60
  text "02/10/2015" at 2357.28,-1794.34 h60
  text "12:12:36 PM" at 3086.28,-1794.34 h60
  text "TEXAS INSTRUMENTS" at 4350.78,-1794.34 h60
M12 Stackup:
  lines w6: 10614,6846.33 13104,6846.33 ; 10614,6963.03 13104,6963.03 ; 10554,6298 ccw(c10592,6298) 10592,6260 13126,6260 ccw(c13126,6298) 13164,6298 13164,7097 ccw(c13126,7097) 13126,7135 10592,7135 ccw(c10592,7097) 10554,7097 10554,6298
  text "Layer Stack Up Detail for: TIDA-00732.PcbDoc" at 10614,7008.02 h55
  text "Layer" at 10614,6919.53 h27
  text "Gerber" at 11493.79,6919.53 h27
  text "Copper" at 12006.9,6919.53 h27
  text "Dielectric" at 12564.1,6919.53 h27
  text "Name" at 10614,6865.53 h27
  text "Document" at 11493.79,6865.53 h27
  text "Thickness" at 12006.9,6865.53 h27
  text "Material" at 12564.1,6865.53 h27
  text "Top Solder Mask" at 10614,6761.3 h38
  text "(.GTS)" at 11493.79,6761.3 h38
  text "Solder Resist" at 12564.1,6761.3 h38
  text "1.4mil" at 12025,6710 h38
  text "Top Layer" at 10620,6700 h38
  text "FR-408" at 12580,6700 h38
  text "(.GTL)" at 11500,6695 h38
  text "1.4mil" at 12025,6650 h38
  text "FR-408" at 12580,6650 h38
  text "GND1" at 10625,6635 h38
  text "(.G1)" at 11500,6630 h38
  text "1.4mil" at 12030,6590 h38
  text "FR-408" at 12580,6585 h38
  text "PWR1" at 10625,6575 h38
  text "(.G2)" at 11500,6555 h38
  text "1.4mil" at 12025,6520 h38
  text "FR-408" at 12585,6520 h38
  text "PWR2" at 10625,6510 h38
  text "(.G3)" at 11505,6490 h38
  text "GND2" at 10625,6445 h38
  text "1.4mil" at 12025,6445 h38
  text "FR-408" at 12585,6440 h38
  text "(.G4)" at 11510,6430 h38
  text "1.4mil" at 12020,6365 h38
  text "Bottom Layer" at 10590,6360 h38
  text "FR-408" at 12595,6360 h38
  text "(.GBL)" at 11520,6355 h38
  text "Bottom Solder Mask" at 10590,6295 h38
  text "Solder Resist" at 12580,6295 h38
  text "(.GBS)" at 11515,6290 h38
M13 Component Bodies Top:
  text ".Layer_Name" at -185.22,-1588.49 h60
M14 Component Bodies Bottom:
  text ".Layer_Name" at -185.22,-1588.49 h60
M15 Courtyards Top:
  text ".Layer_Name" at -185.22,-1588.49 h60
M16 Courtyards Bottom:
  text ".Layer_Name" at -185.22,-1588.49 h60
Drill Drawing:
  text ".legend" at 6612.78,5230 h60
  text "Drill Table" at 6669,5095 h60
  text "FOR 7.874MIL DRILL +0/-7.874MIL" at 6647.78,4854 h60
  text "FOR 12MIL DRILL +0/-12MIL" at 6647.78,4774 h60
  text "FOR 16MIL DRILL +0/-16MIL" at 6647.78,4689 h60
  text "FOR 18MIL DRILL +0/-18MIL" at 6640.78,4601 h60
  text "FOR PTH DRILL +/-3MIL" at 6639,4506 h60
  text "FOR NPTH DRILL +/-2MIL" at 6639,4426 h60
  text "DRILL DRAWING" at -185.22,-1588.49 h60

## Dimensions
8994.78,2722 to 8994.78,1730 on M2 Board Dimensions
8994.78,1730 to 8419.78,1730 on M2 Board Dimensions
8994.78,1730 to 8994.78,0 on M2 Board Dimensions
8994.78,4186 to 8994.78,2722 on M2 Board Dimensions
0,4186 to 0,0 on M2 Board Dimensions
0,0 to 8994.78,0 on M2 Board Dimensions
